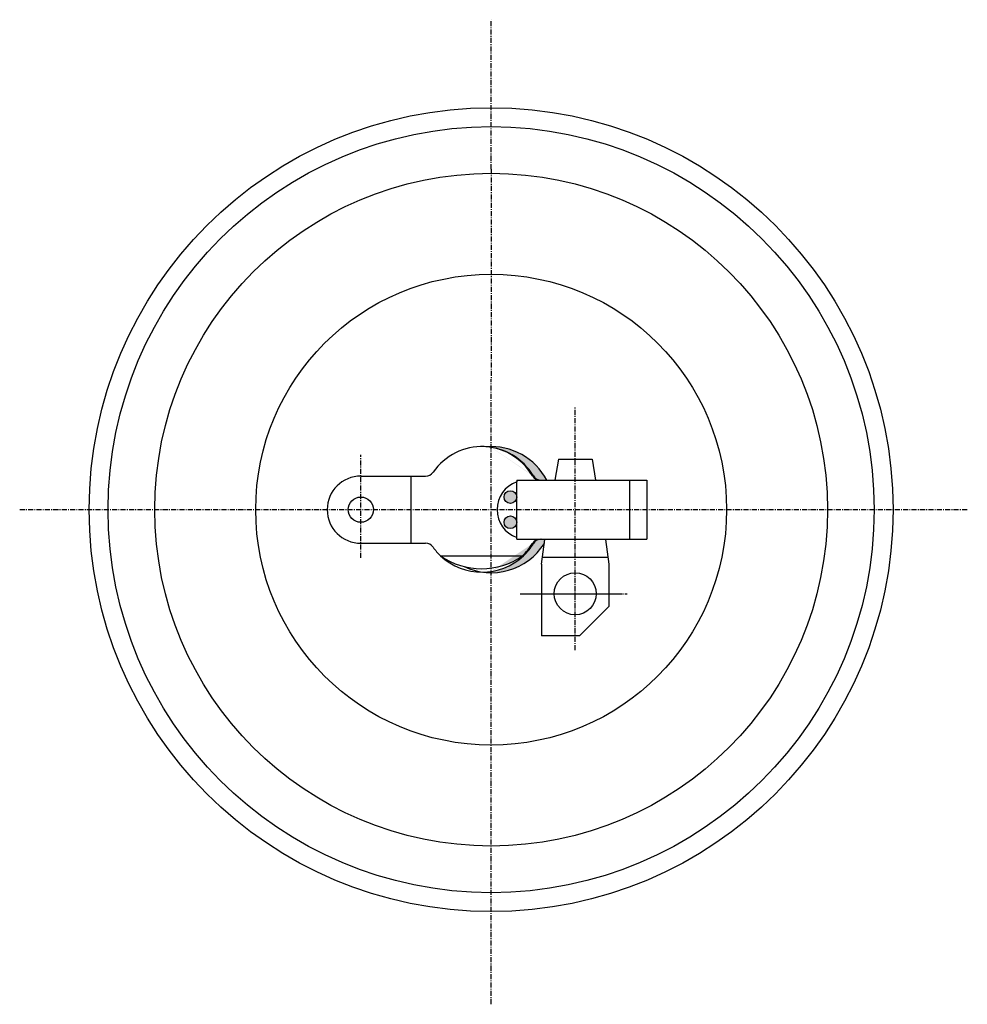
# Model space of a CAD drawing. Units: millimetres. Extents: x -91 to 198, y -189 to 190.
# Drawn here: x -56 to 57, y -189 to -72 of the extents above; entities that cross this region are included whole.
import ezdxf

# ---------------------------------------------------------------- set-up
doc = ezdxf.new("R2010")
doc.units = ezdxf.units.MM
doc.header["$LTSCALE"] = 0.2
doc.linetypes.add('ACAD_ISO10W100', pattern=[18, 12, -3, 0, -3])

msp = doc.modelspace()

# ---------------------------------------------------------------- hatches: boundary and pattern name
at = {"lineweight": 18, "ltscale": 0.25}
h = msp.add_hatch(color=7, dxfattribs=at)
edge = h.paths.add_edge_path()
edge.add_line((0, -122.5), (0, -122.584))
edge.add_ellipse((-1.082, -130), major_axis=(0, 7.5), ratio=0.9659258, start_angle=302.45069, end_angle=351.413, ccw=False)
edge.add_arc((5.969, -125.4), 1.1, 211.55802, 270)
edge.add_line((5.969, -126.5), (6.633, -126.5))
edge.add_arc((0, -130), 7.5, 27.81814, 90)
edge = h.paths.add_edge_path()
edge.add_line((6.33, -134.022), (6.394, -133.544))
edge.add_line((6.394, -133.544), (6.402, -133.5))
edge.add_line((6.402, -133.5), (5.969, -133.5))
edge.add_arc((5.969, -134.6), 1.1, 90, 148.44198)
edge.add_ellipse((-1.082, -130), major_axis=(0, 7.5), ratio=0.9659258, start_angle=222.83343, end_angle=237.54931, ccw=False)
edge.add_arc((-1.082, -130.134), 7.284, 278.54057, 312.54904, ccw=False)
edge.add_line((0, -137.337), (0, -137.5))
edge.add_arc((0, -130), 7.5, 270, 327.57078)
at = {"lineweight": 30, "ltscale": 0.25}
h = msp.add_hatch(color=7, dxfattribs=at)
h.paths.add_polyline_path([(3.044, -131.5, 1), (1.544, -131.5, 1)])
h.paths.add_polyline_path([(3.044, -128.5, 1), (1.544, -128.5, 1)])

# ---------------------------------------------------------------- linework, layer by layer
at = {"color": 1, "linetype": 'ACAD_ISO10W100', "lineweight": 25, "ltscale": 0.25}
for p, q in [((0, -89.5), (0, -71.729)), ((0, -89.5), (0, -114.5)), ((0, -188.826), (0, -114.5)), ((10, -146.709), (10, -117.805)), ((-15.5, -135.735), (-15.5, -123.466)), ((-56.068, -130), (0, -130)), ((0, -130), (56.63, -130)), ((10, -145.735), (10, -133.466)), ((3.47, -140), (15.563, -140)), ((3.892, -140), (16.16, -140))]:
    msp.add_line(p, q, dxfattribs=at)
at = {"color": 7, "lineweight": 30, "ltscale": 0.25}
for p, q in [((8, -124), (7.579, -126.5)), ((8, -124), (12, -124)), ((12, -124), (12.421, -126.5)), ((-15.5, -126), (-7.801, -126)), ((-9.5, -134), (-9.5, -126)), ((3.044, -126.5), (3.044, -126.697)), ((3.044, -126.5), (18.504, -126.5)), ((3.044, -133.303), (3.044, -126.697)), ((16.479, -133.5), (16.479, -126.5)), ((18.504, -126.5), (18.504, -133.5)), ((3.044, -133.5), (3.044, -133.303)), ((-15.5, -134), (-7.801, -134)), ((3.044, -133.5), (18.504, -133.5)), ((6, -136.5), (6.394, -133.544)), ((6.402, -133.5), (6.394, -133.544)), ((13.606, -133.544), (6.394, -133.544)), ((13.598, -133.5), (13.606, -133.544)), ((13.606, -133.544), (14, -136.5)), ((-6.007, -135.5), (3.742, -135.5)), ((6.114, -135.646), (13.886, -135.646)), ((6, -136.5), (6, -145)), ((14, -136.5), (14, -141.5)), ((14, -141.5), (10.5, -145)), ((10.5, -145), (6, -145))]:
    msp.add_line(p, q, dxfattribs=at)
for centre, radius in [((0, -130), 47.8), ((0, -130), 45.55), ((0, -130), 40), ((0, -130), 28), ((-15.5, -130), 1.5), ((-15.5, -130), 1.5), ((2.294, -128.5), 0.75), ((2.294, -131.5), 0.75), ((10, -140), 2.5)]:
    msp.add_circle(centre, radius, dxfattribs=at)
for centre, radius, start, end in [((0, -130), 7.5, 27.81814, 94.2504), ((-15.5, -130), 4, 90, 270), ((-7.801, -124.9), 1.1, 270, 324.45142), ((5.842, -125.4), 1.1, 211.09329, 270), ((5.969, -125.4), 1.1, 211.55802, 270), ((4.202, -130), 3.5, 109.32965, 250.67035), ((-7.801, -135.1), 1.1, 35.54858, 90), ((0, -130), 7.5, 244.53556, 327.57078), ((5.842, -134.6), 1.1, 90, 148.90671), ((5.969, -134.6), 1.1, 90, 148.44198), ((-1.082, -130.134), 7.284, 227.45096, 312.54904), ((-1.133, -128.513), 8.519, 235.0987, 304.9013)]:
    msp.add_arc(centre, radius, start, end, dxfattribs=at)
for ratio, start_param, end_param in [(0.9659258, 5.2787604, 7.2170531), (0.9459258, 5.2799651, 6.2831853), (0.9659258, 2.2077249, 2.3940083), (0.9459258, 10.1723623, 10.4279982), (0.9659258, 3.889177, 4.1460175)]:
    msp.add_ellipse((-1.082, -130), major_axis=(0, 7.5), ratio=ratio, start_param=start_param, end_param=end_param, dxfattribs=at)

doc.saveas('drawing.dxf')
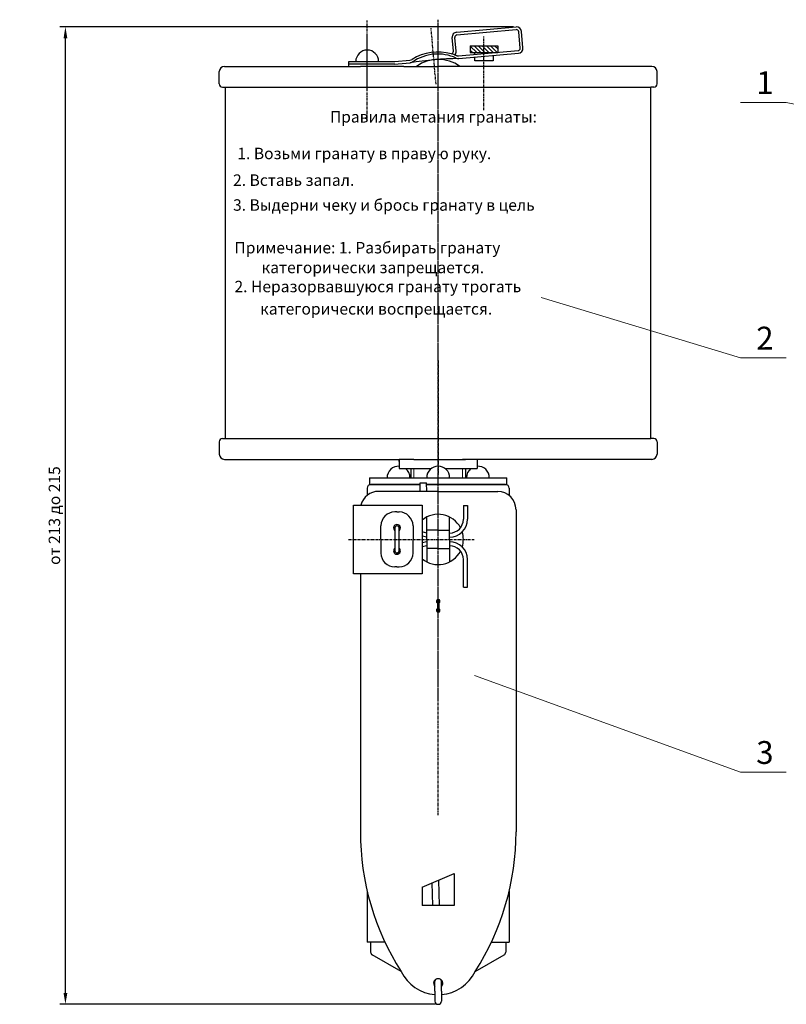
# Model space of a CAD drawing. Units: millimetres. Extents: x -91 to 198, y -189 to 190.
# Drawn here: x -91 to 76, y -26 to 189 of the extents above; entities that cross this region are included whole.
import ezdxf

# ---------------------------------------------------------------- set-up
doc = ezdxf.new("R2010")
doc.units = ezdxf.units.MM
doc.header["$LTSCALE"] = 0.2
doc.linetypes.add('ACAD_ISO02W100', pattern=[15, 12, -3])
doc.linetypes.add('ACAD_ISO10W100', pattern=[18, 12, -3, 0, -3])
doc.dimstyles.new('ISO-25', dxfattribs={"dimtxt": 2.5, "dimasz": 2.5, "dimexe": 1.25, "dimexo": 0.625, "dimtad": 1, "dimtxsty": 'Standard', "dimcen": 2.5, "dimadec": 0, "dimazin": 0, "dimtfac": 1, "dimtmove": 0, "dimatfit": 3, "dimfxl": 0, "dimarcsym": 0})

# ---------------------------------------------------------------- blocks, each defined once
blk = doc.blocks.new('*D17')
at = {"color": 0, "lineweight": -2, "ltscale": 0.25}
for p, q in [((16.47, 187.58), (-82.66, 187.58)), ((-81.41, -23.54), (-81.41, 185.08)), ((-0.62, -26.04), (-82.66, -26.04))]:
    blk.add_line(p, q, dxfattribs=at)
at = {"color": 0, "lineweight": 15, "ltscale": 0.25}
for points in [[(-81.82, 185.08), (-80.99, 185.08), (-81.41, 187.58)], [(-81.82, -23.54), (-80.99, -23.54), (-81.41, -26.04)]]:
    blk.add_solid(points, dxfattribs=at)
at = {"layer": 'Defpoints', "color": 0, "lineweight": 15, "ltscale": 0.25}
for p in [(-81.41, 187.58), (17.09, 187.58), (0, -26.04)]:
    blk.add_point(p, dxfattribs=at)
at = {"color": 0, "lineweight": 15, "ltscale": 0.25, "insert": (-83.49, 80.77), "char_height": 2.5, "attachment_point": 5, "rotation": 90}
blk.add_mtext('от 213 до 215', dxfattribs=at)

msp = doc.modelspace()

# ---------------------------------------------------------------- hatches: boundary and pattern name
at = {"lineweight": 15, "ltscale": 0.25}
h = msp.add_hatch(dxfattribs=at)
h.set_pattern_fill('ANSI31', scale=0.2, angle=90, style=0)
h.paths.add_polyline_path([(10, 183.458), (6.99, 183.458), (6.99, 181.958), (7.597, 181.962), (10, 181.979)])
h.paths.add_polyline_path([(13.01, 183.458), (10, 183.458), (10, 181.979), (13.01, 182.001)])

# ---------------------------------------------------------------- linework, layer by layer
at = {"color": 1, "linetype": 'ACAD_ISO10W100', "lineweight": 25, "ltscale": 0.25}
for p, q in [((-15.5, 167.569), (-15.5, 188.958)), ((-0.468, 175.05), (-1.55, 187.271)), ((0, 114.826), (0, 189.152)), ((0, 114.632), (0, 188.958)), ((-15.5, 173.673), (-15.5, 185.941)), ((10, 169.36), (10, 185.462)), ((0, 40.5), (0, 114.826)), ((0, 114.632), (0, 89.632)), ((0, 15.306), (0, 89.632)), ((-19.616, 75.558), (7.876, 75.558))]:
    msp.add_line(p, q, dxfattribs=at)
at = {"color": 7, "lineweight": 30, "ltscale": 0.25}
for p, q in [((4.047, 186.425), (16.996, 187.572)), ((3.313, 182.245), (3.048, 185.232)), ((3.91, 182.299), (3.646, 185.285)), ((4.1, 185.827), (17.049, 186.974)), ((17.908, 182.937), (17.591, 186.52)), ((18.504, 183.01), (18.189, 186.573)), ((6.99, 183.458), (13.01, 183.458)), ((6.99, 183.458), (6.99, 181.958)), ((13.01, 183.458), (13.01, 182.001)), ((4.424, 181.241), (17.455, 182.394)), ((4.503, 180.666), (17.506, 181.817)), ((6.99, 181.958), (7.597, 181.962)), ((7.597, 181.962), (13.01, 182.001)), ((8, 181.562), (8, 181.557)), ((8, 180.158), (8, 180.975)), ((12, 181.33), (12, 180.158)), ((-46.675, 178.958), (-27.79, 178.958)), ((-27.79, 178.958), (-17, 178.958)), ((-19.5, 179.408), (-19.5, 180.008)), ((-19.5, 180.008), (-9.5, 180.008)), ((-19.5, 178.958), (-19.5, 179.408)), ((-11.5, 179.408), (-19.5, 179.408)), ((-9.5, 179.408), (-19.5, 179.408)), ((-14, 178.958), (-17, 178.958)), ((-7.5, 178.958), (-14, 178.958)), ((-9.604, 179.417), (-6.143, 179.723)), ((-9.5, 180.008), (-6.17, 180.303)), ((-7.5, 178.958), (0, 178.958)), ((-6.143, 179.723), (-6.137, 179.724)), ((7.5, 178.958), (0, 178.958)), ((14, 178.958), (6, 178.958)), ((27.79, 178.958), (7.5, 178.958)), ((12, 180.158), (8, 180.158)), ((46.675, 178.958), (27.79, 178.958)), ((-47.8, 175.108), (-47.8, 177.833)), ((47.8, 175.108), (47.8, 177.833)), ((-47.125, 174.433), (-46.45, 174.433)), ((-46.45, 97.583), (-46.45, 174.433)), ((-46.45, 174.433), (46.45, 174.433)), ((47.125, 174.433), (46.45, 174.433)), ((46.45, 97.583), (46.45, 174.433)), ((-47.8, 96.908), (-47.8, 94.183)), ((-47.125, 97.583), (-46.45, 97.583)), ((-46.45, 97.583), (46.45, 97.583)), ((47.125, 97.583), (46.45, 97.583)), ((47.8, 96.908), (47.8, 94.183)), ((-46.681, 93.058), (-27.79, 93.058)), ((-27.79, 93.058), (-8.499, 93.058)), ((-8.5, 93.058), (-8.499, 93.058)), ((-8.5, 92.608), (-8.5, 93.058)), ((-8.5, 93.058), (-8.5, 91.058)), ((-6, 93.058), (-8.5, 93.058)), ((-5.3, 93.058), (-6, 93.058)), ((-5.3, 93.058), (5.3, 93.058)), ((6, 93.058), (5.3, 93.058)), ((5.3, 93.058), (6, 93.058)), ((8.5, 93.058), (6, 93.058)), ((27.79, 93.058), (8.5, 93.058)), ((8.5, 93.058), (8.5, 92.608)), ((8.5, 93.058), (8.5, 91.058)), ((46.675, 93.058), (27.79, 93.058)), ((-8.5, 91.058), (-1.5, 91.058)), ((-6, 91.058), (-6, 89.058)), ((1.5, 91.058), (8.5, 91.058)), ((6, 91.058), (6, 89.058)), ((-15, 89.058), (15, 89.058)), ((-15, 89.058), (-15, 87.558)), ((15, 87.558), (15, 89.058)), ((-15.5, 86.758), (-15.5, 85.18)), ((-15, 87.558), (-3.945, 87.558)), ((-3.945, 87.558), (-14.7, 87.558)), ((-3.9, 86.058), (-3.957, 87.958)), ((-3.957, 87.958), (-2.557, 87.958)), ((-2.5, 86.058), (-2.557, 87.958)), ((-2.5, 87.558), (-2.545, 87.558)), ((14.7, 87.558), (-2.5, 87.558)), ((-2.5, 87.558), (15, 87.558)), ((15.5, 86.758), (15.5, 85.18)), ((0, 86.058), (-13, 86.058)), ((0, 86.058), (13, 86.058)), ((-18.5, 68.058), (-18.5, 83.058)), ((-18.5, 83.058), (-3.5, 83.058)), ((-3.5, 83.058), (-3.5, 68.058)), ((5.5, 82.958), (6.4, 82.958)), ((5.5, 82.958), (5.5, 79.958)), ((6.4, 82.958), (6.4, 79.958)), ((17, 82.058), (17, 11.661)), ((-9, 81.558), (-9.5, 81.558)), ((-9, 81.558), (-8.5, 81.558)), ((-2.5, 75.558), (-2.5, 80.457)), ((2.5, 75.558), (2.5, 80.457)), ((-12.5, 75.558), (-12.5, 78.558)), ((-9.45, 78.058), (-9.45, 73.058)), ((-8.311, 78.355), (-8.895, 78.495)), ((-8.55, 73.058), (-8.55, 78.058)), ((-8.52, 77.482), (-8.55, 77.489)), ((-5.5, 78.558), (-5.5, 75.558)), ((0, 77.558), (-2.5, 77.558)), ((0, 77.558), (2.5, 77.558)), ((-12.5, 75.558), (-12.5, 72.558)), ((-5.5, 72.558), (-5.5, 75.558)), ((-2.5, 76.958), (-3.5, 77.198)), ((-2.5, 76.058), (-3.5, 76.294)), ((-2.5, 75.558), (-2.5, 70.659)), ((2.5, 75.558), (2.5, 70.659)), ((-8.52, 73.634), (-8.55, 73.627)), ((-2.5, 75.058), (-3.5, 74.821)), ((-2.5, 74.158), (-3.5, 73.917)), ((0, 73.558), (-2.5, 73.558)), ((0, 73.558), (2.5, 73.558)), ((-8.311, 72.761), (-8.895, 72.62)), ((5.5, 65.158), (5.5, 71.158)), ((6.4, 65.158), (6.4, 71.158)), ((-9, 69.558), (-9.5, 69.558)), ((-9, 69.558), (-8.5, 69.558)), ((-3.5, 68.058), (-18.5, 68.058)), ((-17, 68.058), (-17, 11.661)), ((5.5, 65.158), (6.4, 65.158)), ((-0.15, 62.058), (-0.15, 60.058)), ((0.15, 62.058), (0.15, 60.058)), ((-3.5, -0.442), (3.5, 2.558)), ((3.5, 2.558), (3.5, -4.442)), ((-1.195, -4.442), (-1.342, 0.483)), ((0.04, 1.075), (0.205, -4.442)), ((-15.5, -1.307), (-15.5, -12.442)), ((-3.5, -0.442), (-3.5, -4.442)), ((15.5, -1.307), (15.5, -12.442)), ((3.5, -4.442), (-3.5, -4.442)), ((-11.633, -12.442), (-15.5, -12.442)), ((-14.75, -12.442), (-14.75, -14.63)), ((11.633, -12.442), (15.5, -12.442)), ((14.75, -12.442), (14.75, -14.63)), ((-8.094, -18.877), (-14.4, -15.237)), ((8.094, -18.877), (14.4, -15.237)), ((-0.7, -23.192), (-0.7, -20.986)), ((0.7, -23.192), (0.7, -20.992)), ((-0.7, -23.192), (-0.7, -25.342)), ((0.7, -23.192), (0.7, -25.342))]:
    msp.add_line(p, q, dxfattribs=at)
at = {"color": 7, "linetype": 'ACAD_ISO02W100', "lineweight": 25, "ltscale": 0.25}
msp.add_line((8, 181.958), (8, 181.965), dxfattribs=at)
at = {"color": 7, "lineweight": 15, "ltscale": 0.25}
for p, q in [((66.022, 171.087), (76.022, 171.087)), ((76.022, 171.087), (148.204, 156.278)), ((66.022, 115.259), (22.469, 128.446)), ((66.022, 115.259), (76.022, 115.259)), ((-5.3, 91.058), (-5.3, 89.058)), ((5.3, 91.058), (5.3, 89.058)), ((66.022, 24.701), (7.952, 45.802)), ((66.022, 24.701), (76.022, 24.701))]:
    msp.add_line(p, q, dxfattribs=at)
at = {"color": 7, "lineweight": 30, "ltscale": 0.25}
for centre, radius, start, end in [((17.093, 186.476), 1.1, 5.06, 95.06), ((4.144, 185.329), 1.1, 95.06, 185.06), ((4.144, 185.329), 0.5, 95.06, 185.06), ((17.093, 186.476), 0.5, 5.06, 95.06), ((17.41, 182.893), 0.5, 275.06, 5.06), ((17.409, 182.913), 1.1, 275.06, 5.06), ((-15.5, 180.008), 2.5, 0, 180), ((-0.055, 171.551), 10.543, 74.25589, 122.24423), ((-0.083, 171.875), 9.758, 65.57806, 124.54194), ((2.815, 182.201), 0.5, 275.06, 5.06), ((-2.301, 165.972), 16.556, 67.95295, 71.84305), ((2.814, 182.202), 1.1, 315.98814, 5.06), ((-0.055, 171.551), 10.543, 66.46415, 69.6852), ((4.327, 182.336), 1.1, 247.95295, 275.06), ((7.6, 181.562), 0.4, 0, 90.41011), ((-46.675, 177.833), 1.125, 90, 180), ((-6.267, 181.398), 1.1, 275.06, 302.24423), ((-6.24, 180.819), 1.1, 275.06, 304.54194), ((5.624, 107.564), 73.111, 90.8788, 99.23559), ((4.406, 181.762), 1.1, 245.57806, 275.06), ((46.675, 177.833), 1.125, 0, 90), ((-47.125, 175.108), 0.675, 180, 270), ((47.125, 175.108), 0.675, 270, 0), ((-47.125, 96.908), 0.675, 90, 180), ((47.125, 96.908), 0.675, 0, 90), ((-46.675, 94.183), 1.125, 180, 270), ((-47, 94.508), 1.45, 276.78123, 276.84585), ((46.675, 94.183), 1.125, 270, 0), ((-8.66, 89.058), 2.5, 86.32473, 180), ((-8.66, 89.058), 2.5, 0, 53.1301), ((0, 89.058), 2.5, 0, 180), ((8.66, 89.058), 2.5, 126.8699, 180), ((8.66, 89.058), 2.5, 0, 93.67527), ((-14.7, 86.758), 0.8, 90, 180), ((14.7, 86.758), 0.8, 0, 90), ((-13, 82.058), 4, 90, 165.52249), ((13, 82.058), 4, 0, 90), ((-9.5, 78.558), 3, 90, 180), ((-8.5, 78.558), 3, 0, 90), ((0, 75.558), 5.5, 27.72539, 129.5212), ((2.5, 79.958), 3, 270, 0), ((2.5, 79.958), 3.9, 270, 0), ((-9, 78.058), 0.75, 306.8699, 233.1301), ((-9, 78.058), 0.45, 0, 180), ((0, 75.558), 5.5, 342.69829, 17.30171), ((-9, 73.058), 0.75, 126.8699, 53.1301), ((2.5, 71.158), 3.9, 0, 90), ((2.5, 71.158), 3, 0, 90), ((-9.5, 72.558), 3, 180, 270), ((-9, 73.058), 0.45, 180, 0), ((-8.5, 72.558), 3, 270, 0), ((0, 75.558), 5.5, 230.4788, 332.27461), ((0, 62.058), 0.4, 292.02431, 247.97569), ((0, 60.058), 0.4, 112.02431, 67.97569), ((0, 62.058), 0.15, 0, 180), ((0, 60.058), 0.15, 180, 0), ((39.812, 11.661), 56.812, 180, 212.51617), ((-39.812, 11.661), 56.812, 327.48383, 0), ((-14.05, -14.63), 0.7, 180, 240), ((14.05, -14.63), 0.7, 300, 0), ((0, -14.942), 9, 205.92801, 265.53916), ((0, -14.942), 9, 274.46084, 334.07199), ((0, -21.442), 1, 314.427, 225.573), ((0, -20.992), 0.7, 150.78454, 180), ((0, -20.992), 0.7, 0, 29.21546), ((0, -25.342), 0.7, 180, 0)]:
    msp.add_arc(centre, radius, start, end, dxfattribs=at)
at = {"color": 7, "linetype": 'ByBlock', "lineweight": 30}
msp.add_arc((0, 172.258), 8.2, 54.79287, 125.20713, dxfattribs=at)

# ---------------------------------------------------------------- texts
at = {"color": 7, "lineweight": 15, "ltscale": 0.25}
for s, p in [('1', (69.455, 172.876)), ('2', (69.455, 117.047)), ('3', (69.455, 26.489))]:
    msp.add_text(s, height=5, dxfattribs=at).set_placement(p)
at = {"color": 7, "lineweight": 30, "ltscale": 0.25}
for s, p in [('Правила метания гранаты:', (-23.643, 166.672)), ('1. Возьми гранату в правую руку.', (-43.865, 158.667)), ('2. Вставь запал.', (-44.798, 152.839)), ('3. Выдерни чеку и брось гранату в цель', (-44.798, 147.398)), ('Примечание: 1. Разбирать гранату', (-44.487, 138.073)), ('категорически запрещается.', (-38.576, 133.75)), ('2. Неразорвавшуюся гранату трогать', (-44.487, 129.584)), ('категорически воспрещается.', (-38.887, 124.705))]:
    msp.add_text(s, height=2.5, dxfattribs=at).set_placement(p)

# ---------------------------------------------------------------- dimensions: what is measured, and where the dimension line sits
at = {"color": 3, "lineweight": 15, "ltscale": 0.25}
dim = msp.add_linear_dim(base=(-81.405, 187.576), p1=(0, -26.042), p2=(17.093, 187.576), angle=90, text='от 213 до 215', dimstyle='ISO-25', dxfattribs=at)
dim.commit()
dim.dimension.update_dxf_attribs({"geometry": '*D17', "text_midpoint": (-83.489, 80.767)})

doc.saveas('drawing.dxf')
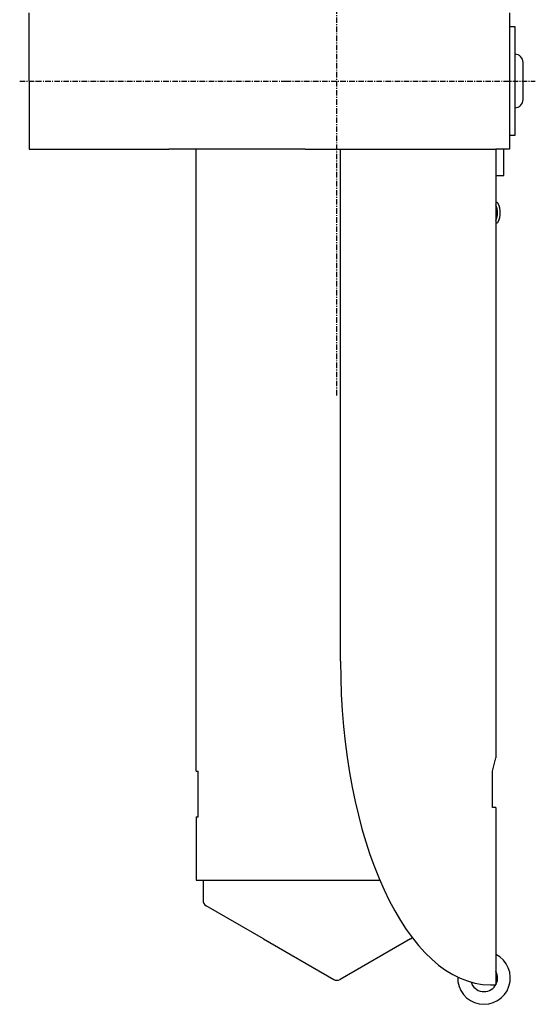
# Model space of a CAD drawing. Units: millimetres. Extents: x -91 to 198, y -189 to 190.
# Drawn here: x 115 to 172, y -26 to 82 of the extents above; entities that cross this region are included whole.
import ezdxf

# ---------------------------------------------------------------- set-up
doc = ezdxf.new("R2010")
doc.units = ezdxf.units.MM
doc.header["$LTSCALE"] = 0.2
doc.linetypes.add('ACAD_ISO10W100', pattern=[18, 12, -3, 0, -3])

msp = doc.modelspace()

# ---------------------------------------------------------------- linework, layer by layer
at = {"color": 1, "linetype": 'ACAD_ISO10W100', "lineweight": 25, "ltscale": 0.25}
for p, q in [((150, 40.94999999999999), (150, 115.2760053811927)), ((115.0527369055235, 75.55779463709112), (116.8716337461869, 75.55779463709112)), ((116.8716337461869, 75.55779463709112), (144.3634335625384, 75.55779463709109)), ((144.3634335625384, 75.55779463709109), (171.8552333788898, 75.55779463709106))]:
    msp.add_line(p, q, dxfattribs=at)
at = {"color": 7, "lineweight": 30, "ltscale": 0.25}
for p, q in [((116.1, 75.55779463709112), (116.1, 83.05779463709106)), ((169.0000030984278, 83.05779463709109), (169.0000030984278, 68.05779463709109)), ((169.0000030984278, 81.55779463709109), (169.6000030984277, 81.55779463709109)), ((169.6000030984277, 81.55779463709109), (169.6000030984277, 69.55779463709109)), ((170.5000030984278, 73.50779463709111), (170.5000030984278, 77.60779463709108)), ((116.1, 75.55779463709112), (116.1, 68.05779463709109)), ((169.6000030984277, 69.55779463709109), (169.0000030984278, 69.55779463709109)), ((116.1, 68.05779463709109), (131.5, 68.05779463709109)), ((146.5, 68.05779463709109), (131.5, 68.05779463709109)), ((134.5, -0.4422053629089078), (134.5, 68.05779463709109)), ((146.5, 68.05779463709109), (167.5000030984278, 68.05779463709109)), ((150.4000030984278, 11.68323594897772), (150.4000030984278, 68.05779463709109)), ((169.0000030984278, 68.05779463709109), (167.5000030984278, 68.05779463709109)), ((167.5000030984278, 68.05779463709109), (167.5000030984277, 1.057794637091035)), ((168.4000030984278, 65.15779463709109), (168.4000030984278, 68.05779463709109)), ((167.5000030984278, 65.15779463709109), (168.4000030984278, 65.15779463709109)), ((167.1400042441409, -0.4431136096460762), (167.5000030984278, 1.057794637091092)), ((134.5, -0.4422053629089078), (134.7, -0.4422053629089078)), ((134.7, -5.442205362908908), (134.7, -0.4422053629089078)), ((167.1400030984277, -4.442205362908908), (167.1400042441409, -0.4431136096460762)), ((167.5000030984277, -4.442205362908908), (167.1400030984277, -4.442205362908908)), ((167.5000030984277, -4.442205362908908), (167.5000030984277, -23.94220536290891)), ((134.5, -5.442205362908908), (134.7, -5.442205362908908)), ((134.5, -5.442205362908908), (134.5, -12.44220536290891)), ((134.5, -12.44220536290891), (154.7296343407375, -12.44220536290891)), ((135.25, -12.44220536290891), (135.25, -14.63044685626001)), ((141.9059031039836, -18.87737949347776), (135.6, -15.23666463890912)), ((141.9059031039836, -18.87737949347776), (149.6500007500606, -23.34842357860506)), ((158.0940968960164, -18.87737949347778), (150.3499992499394, -23.34842357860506)), ((158.0940968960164, -18.87737949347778), (158.3052730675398, -18.75545687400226)), ((166.9000030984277, -23.94220536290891), (167.4990302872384, -23.94388780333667))]:
    msp.add_line(p, q, dxfattribs=at)
for centre, radius, start, end in [((169.6000030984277, 77.60779463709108), 0.9, 0, 90), ((169.6000030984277, 73.50779463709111), 0.9, 270, 0), ((165.7982421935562, 61.05779463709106), 1.9, 333.4586685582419, 26.54133144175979), ((167.5000030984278, 61.90779463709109), 0.3000000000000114, 29.9999999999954, 90), ((165.7982421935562, 61.05779463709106), 2.201760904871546, 332.9876899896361, 27.0123100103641), ((167.5000030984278, 60.2077946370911), 0.3000000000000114, 270, 329.9999999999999), ((135.95, -14.63044685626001), 0.7, 180, 239.9999999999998), ((166.2009649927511, -23.19220536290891), 2.9, 177.8820447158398, 63.38813937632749), ((166.2009649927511, -23.19220536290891), 1.5, 197.4351235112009, 30), ((150, -22.7422053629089), 0.7, 240.0000708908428, 299.9999291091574)]:
    msp.add_arc(centre, radius, start, end, dxfattribs=at)
msp.add_ellipse((167, 11.66135114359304), major_axis=(-0.09999690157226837, -35.60355650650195), ratio=0.4662436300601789, start_param=4.713083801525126, end_param=6.283185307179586, dxfattribs=at)

doc.saveas('drawing.dxf')
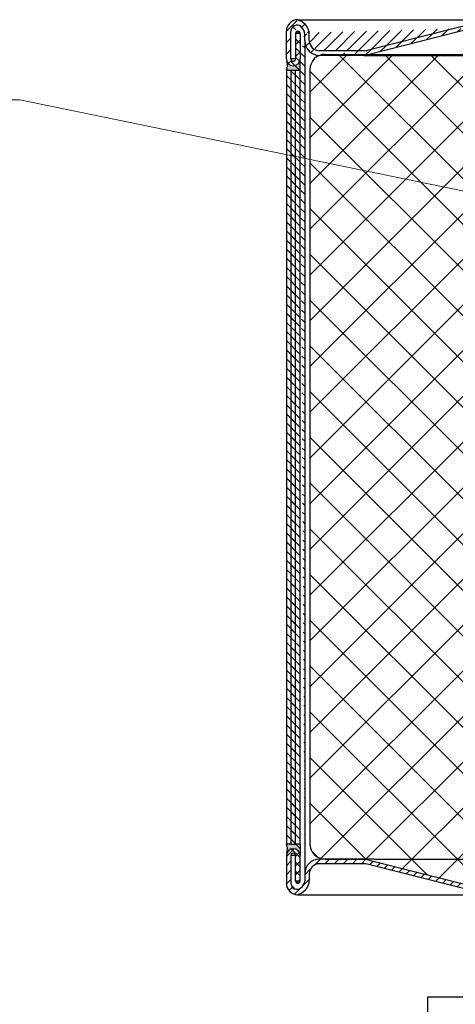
# Model space of a CAD drawing. Units: millimetres. Extents: x -91 to 198, y -189 to 190.
# Drawn here: x 76 to 119, y 82 to 179 of the extents above; entities that cross this region are included whole.
import ezdxf

# ---------------------------------------------------------------- set-up
doc = ezdxf.new("R2010")
doc.units = ezdxf.units.MM
doc.header["$LTSCALE"] = 0.2
pattern_1 = [(135, (0, 0), (-0.4490128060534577, -0.4490128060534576), [])]

msp = doc.modelspace()

# ---------------------------------------------------------------- hatches: boundary and pattern name
at = {"lineweight": 15, "ltscale": 0.25}
h = msp.add_hatch(dxfattribs=at)
h.set_pattern_fill('ANSI31', scale=0.25, style=0)
h.set_pattern_definition([(45, (150, 0), (-0.561266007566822, 0.5612660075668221), [])])
edge = h.paths.add_edge_path()
edge.add_line((103.55, 177.6077946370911), (103.1, 177.6077946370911))
edge.add_line((103.55, 177.6077946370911), (103.55, 175.1077946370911))
edge.add_line((103.1, 177.6077946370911), (103.1, 175.1077946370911))
edge.add_arc((102.875, 175.1077946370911), 0.6750000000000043, 180, 360)
edge.add_arc((102.875, 175.1077946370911), 0.2250000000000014, 180, 360)
edge.add_line((102.65, 175.1077946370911), (102.65, 177.6077946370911))
edge.add_line((102.2, 175.1077946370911), (102.2, 177.8327946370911))
edge.add_arc((103.325, 177.8327946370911), 1.125, 90, 180)
edge.add_arc((103.25, 177.8200445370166), 0.6, 51.31781254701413, 180)
edge.add_arc((103, 177.5077946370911), 1.45, 0, 83.21876594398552)
edge.add_arc((103, 177.5077946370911), 1, 0, 51.31781254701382)
edge.add_line((104, 176.9077946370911), (104, 177.5077946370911))
edge.add_line((104.4499998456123, 176.9077947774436), (104.45, 177.5077946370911))
edge.add_arc((105.45, 176.9077946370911), 1.45, 180, 270)
edge.add_arc((105.4499998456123, 176.9077946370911), 1, 179.9999919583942, 270)
edge.add_line((109.855185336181, 175.9077946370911), (105.4499998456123, 175.9077946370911))
edge.add_line((109.7900187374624, 175.4577946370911), (105.45, 175.4577946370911))
edge.add_arc((109.855185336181, 176.9077946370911), 1, 270, 286.4799732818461)
edge.add_arc((109.7900187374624, 176.9077946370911), 1.45, 269.9999999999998, 286.4799732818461)
edge.add_line((121.8611344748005, 178.4667135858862), (110.2013550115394, 175.5173621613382))
edge.add_line((121.7986449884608, 178.898227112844), (110.1388655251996, 175.9488756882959))
edge.add_arc((122.2099812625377, 177.5077946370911), 1.45, 90, 106.4799732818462)
edge.add_arc((122.1448146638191, 177.5077946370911), 1, 90, 106.4799732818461)
edge.add_line((133, 178.5077946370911), (122.1448146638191, 178.5077946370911))
edge.add_line((122.2099812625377, 178.9577946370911), (133, 178.9577946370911))
edge.add_line((133, 178.9577946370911), (133, 178.5077946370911))
h = msp.add_hatch(dxfattribs=at)
h.set_pattern_fill('ANSI31', scale=0.2, angle=90, style=0)
h.set_pattern_definition(pattern_1)
edge = h.paths.add_edge_path()
edge.add_line((103.1, 175.1077946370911), (102.65, 175.1077946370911))
edge.add_line((103.1, 177.6077946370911), (103.1, 175.1077946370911))
edge.add_line((102.65, 175.1077946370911), (102.65, 177.6077946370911))
edge.add_arc((103.25, 177.8200445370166), 0.6, 51.31781254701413, 180)
edge.add_arc((103.325, 177.6077946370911), 0.2250000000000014, 0, 180)
edge.add_line((103.55, 177.6077946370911), (103.55, 175.1077946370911))
edge.add_arc((103, 177.5077946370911), 1, 0, 51.31781254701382)
edge.add_line((104, 176.9077946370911), (104, 177.5077946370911))
edge.add_line((104, 176.9077946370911), (104, 94.40779463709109))
edge.add_line((103.55, 174.0127946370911), (103.55, 175.1077946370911))
edge.add_line((103.55, 98.01279463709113), (103.55, 174.0127946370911))
edge.add_line((103.55, 98.01279463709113), (103.55, 96.90779463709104))
edge.add_line((103.55, 94.40779463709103), (103.55, 96.90779463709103))
edge.add_arc((103.325, 94.40779463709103), 0.2250000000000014, 180, 360)
edge.add_arc((103.25, 94.19554473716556), 0.6, 180, 308.6821874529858)
edge.add_line((102.65, 94.40779463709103), (102.65, 94.19554473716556))
edge.add_line((102.65, 96.90779463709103), (102.65, 94.40779463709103))
edge.add_line((103.1, 94.40779463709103), (103.1, 96.90779463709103))
edge.add_line((103.1, 96.90779463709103), (102.65, 96.90779463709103))
for points in [[(103.55, 175.1077946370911, -0.8066543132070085), (102.2604534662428, 174.8285858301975, -0.159301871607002), (102.2, 174.0127946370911), (102.65, 174.0127946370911), (103.1, 174.0127946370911), (103.55, 174.0127946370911)], [(103.55, 98.01279463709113), (103.1, 98.01279463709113), (102.65, 98.01279463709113), (102.2, 98.01279463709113, -0.1703818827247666), (102.2427745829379, 97.14426032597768, -0.08957544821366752), (102.3654272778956, 97.35046905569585, -0.693844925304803), (103.55, 96.90779463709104)]]:
    msp.add_hatch(color=7, dxfattribs=at).paths.add_polyline_path(points)
h = msp.add_hatch(dxfattribs=at)
h.set_pattern_fill('ANSI37', style=0)
h.set_pattern_definition([(45, (0, 0), (-2.245064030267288, 2.245064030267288), []), (135, (0, 0), (-2.245064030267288, -2.245064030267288), [])])
edge = h.paths.add_edge_path()
edge.add_line((143.5, 173.5577946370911), (141.6, 175.4577946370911))
edge.add_line((141.6, 175.4577946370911), (109.7900187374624, 175.4577946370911))
edge.add_line((109.7900187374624, 175.4577946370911), (105.4614835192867, 175.4577946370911))
edge.add_arc((106, 174.057794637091), 1.5, 111.0394697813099, 180)
edge.add_line((104.5, 174.057794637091), (104.5, 98.05779463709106))
edge.add_arc((106, 98.05779463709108), 1.5, 180.0000000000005, 270)
edge.add_line((106, 96.55779463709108), (109.7900187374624, 96.55779463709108))
edge.add_arc((109.7900187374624, 95.10779463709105), 1.450000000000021, 73.52002671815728, 90, ccw=False)
edge.add_line((110.2013550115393, 96.49822711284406), (120, 94.01965128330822))
edge.add_line((120, 94.01965128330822), (120, 94.69779463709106))
edge.add_line((120, 94.69779463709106), (120, 96.55779463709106))
edge.add_line((120, 96.55779463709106), (137.9871730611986, 96.55779463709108))
edge.add_spline(control_points=[(137.9871730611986, 96.55779463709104), (138.0397711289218, 96.90154095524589), (138.0998945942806, 97.24357800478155), (138.172001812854, 97.58279463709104)], knot_values=[3.513574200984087, 3.513574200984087, 3.513574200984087, 3.513574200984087, 4.553471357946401, 4.553471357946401, 4.553471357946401, 4.553471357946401], degree=3, periodic=0)
edge.add_spline(control_points=[(138.172001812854, 97.58279463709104), (138.3326873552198, 98.33871352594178), (138.9005402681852, 100.2520026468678), (140.7570590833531, 102.7504300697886), (142.6575824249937, 103.3928231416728), (143.5000000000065, 103.5745058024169)], knot_values=[4.553471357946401, 4.553471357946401, 4.553471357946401, 4.553471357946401, 6.870804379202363, 10.52954648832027, 13.14244180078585, 13.14244180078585, 13.14244180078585, 13.14244180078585], degree=3, periodic=0)
edge.add_line((143.5, 103.5745058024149), (143.5, 173.5577946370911))
edge = h.paths.add_edge_path()
edge.add_arc((194, 174.0577946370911), 1.5, 0, 68.9605302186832)
edge.add_line((194.5385164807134, 175.4577946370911), (190.2099812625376, 175.4577946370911))
edge.add_line((190.2099812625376, 175.4577946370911), (158.4000000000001, 175.4577946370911))
edge.add_line((158.4000000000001, 175.4577946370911), (156.5, 173.557794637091))
edge.add_line((156.5, 173.557794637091), (156.5, 107.293329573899))
edge.add_spline(control_points=[(156.5, 107.293329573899), (159.568356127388, 107.2734474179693), (166.2472937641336, 100.5987291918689), (177.8374551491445, 99.56551382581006), (187.1937075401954, 102.0382007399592), (193.2277025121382, 104.4777862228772), (195.4999999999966, 103.8812710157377)], knot_values=[26.56510633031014, 26.56510633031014, 26.56510633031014, 26.56510633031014, 36.92141533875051, 50.22349476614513, 59.82893242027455, 67.1271089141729, 67.1271089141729, 67.1271089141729, 67.1271089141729], degree=3, periodic=0)
edge.add_line((195.5, 103.8812710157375), (195.5, 174.0577946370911))
h = msp.add_hatch(dxfattribs=at)
h.set_pattern_fill('ANSI31', scale=0.2, angle=90, style=0)
h.set_pattern_definition(pattern_1)
h.paths.add_polyline_path([(102.2, 174.0127946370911), (102.2, 98.01279463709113), (102.65, 98.01279463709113), (103.1, 98.01279463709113), (103.55, 98.01279463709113), (103.55, 174.0127946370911), (103.1, 174.0127946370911), (102.65, 174.0127946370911)])
h = msp.add_hatch(dxfattribs=at)
h.set_pattern_fill('ANSI31', scale=0.2, style=0)
h.set_pattern_definition([(45, (0, 0), (-0.4490128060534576, 0.4490128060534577), [])])
edge = h.paths.add_edge_path()
edge.add_arc((102.875, 96.90779463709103), 0.2249999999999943, 0, 180, ccw=False)
edge.add_line((103.1, 96.90779463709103), (103.1, 94.40779463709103))
edge.add_line((103.1, 94.40779463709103), (103.55, 94.40779463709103))
edge.add_line((103.55, 94.40779463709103), (103.55, 96.90779463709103))
edge.add_arc((102.875, 96.90779463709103), 0.6750000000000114, 0, 180)
edge.add_line((102.2, 96.90779463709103), (102.2, 94.18279463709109))
edge.add_arc((103.325, 94.18279463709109), 1.125, 180, 262.2266208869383)
edge.add_arc((103, 94.5077946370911), 1.450000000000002, 276.8458494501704, 360.0000147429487)
edge.add_line((104.45, 94.50779501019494), (104.4499998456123, 95.10779437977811))
edge.add_arc((105.4499998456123, 95.1077946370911), 0.9999999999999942, 90, 180.0000147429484, ccw=False)
edge.add_line((105.4499998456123, 96.10779463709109), (109.855185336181, 96.1077946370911))
edge.add_arc((109.855185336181, 95.1077946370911), 0.9999999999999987, 73.52002671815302, 90.0000000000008, ccw=False)
edge.add_line((110.1388655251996, 96.06671358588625), (121.7986449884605, 93.11736216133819))
edge.add_arc((122.2099812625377, 94.50779463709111), 1.450000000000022, 253.5200267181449, 270)
edge.add_line((122.2099812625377, 93.05779463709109), (137.5397852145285, 93.05779463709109))
edge.add_spline(control_points=[(137.5397852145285, 93.05779463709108), (137.5627773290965, 93.20743537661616), (137.5843313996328, 93.35746623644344), (137.6048188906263, 93.5077946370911)], knot_values=[0, 0, 0, 0, 0.4541903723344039, 0.4541903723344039, 0.4541903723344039, 0.4541903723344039], degree=3, periodic=0)
edge.add_line((137.6048188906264, 93.50779463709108), (132.2171286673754, 93.50779463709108))
edge.add_line((132.2171286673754, 93.50779463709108), (122.1448146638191, 93.5077946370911))
edge.add_arc((122.1448146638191, 94.5077946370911), 0.9999999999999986, 253.52002671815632, 269.9999999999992, ccw=False)
edge.add_line((121.8611344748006, 93.54887568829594), (110.2013550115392, 96.49822711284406))
edge.add_arc((109.7900187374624, 95.10779463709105), 1.450000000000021, 73.52002671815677, 89.99999999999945)
edge.add_line((109.7900187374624, 96.55779463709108), (105.45, 96.55779463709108))
edge.add_arc((105.45, 95.10779463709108), 1.450000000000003, 90.00000000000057, 180)
edge.add_line((104, 95.10779463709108), (104, 94.5077946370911))
edge.add_line((104, 94.5077946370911), (104, 94.40779463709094))
edge.add_arc((103.0620265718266, 94.48096639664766), 0.940823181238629, 306.7542392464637, 355.53936257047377, ccw=False)
edge.add_arc((103.25, 94.19554473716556), 0.5999999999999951, 180, 308.68218745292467, ccw=False)
edge.add_line((102.65, 94.19554473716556), (102.65, 94.40779463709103))
edge.add_line((102.65, 94.40779463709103), (102.65, 96.90779463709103))

# ---------------------------------------------------------------- linework, layer by layer
at = {"color": 7, "lineweight": 30, "ltscale": 0.25}
for p, q in [((103.325, 178.9577946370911), (122.2099812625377, 178.9577946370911)), ((121.7986449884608, 178.898227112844), (110.1388655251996, 175.9488756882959)), ((121.8611344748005, 178.4667135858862), (110.2013550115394, 175.5173621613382)), ((102.2, 175.1077946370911), (102.2, 177.8327946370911)), ((102.65, 177.6077946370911), (102.65, 177.8200445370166)), ((102.65, 175.1077946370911), (102.65, 177.6077946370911)), ((103.55, 177.6077946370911), (103.1, 177.6077946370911)), ((103.1, 177.6077946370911), (103.1, 175.1077946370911)), ((103.55, 177.6077946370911), (103.55, 175.1077946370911)), ((104, 176.9077946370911), (104, 177.5077946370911)), ((104, 176.9077946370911), (104, 94.40779463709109)), ((104.4499998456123, 176.9077947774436), (104.45, 177.5077946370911)), ((104.45, 177.5077946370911), (104.45, 177.5077946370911)), ((109.855185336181, 175.9077946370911), (105.4499998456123, 175.9077946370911)), ((103.1, 175.1077946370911), (102.65, 175.1077946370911)), ((103.55, 174.0127946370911), (103.55, 175.1077946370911)), ((109.7900187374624, 175.4577946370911), (105.45, 175.4577946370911)), ((106, 175.557794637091), (143.55, 175.557794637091)), ((109.7900187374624, 175.4577946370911), (143.55, 175.4577946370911)), ((102.2, 174.0127946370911), (102.65, 174.0127946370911)), ((102.2, 174.0127946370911), (102.2, 98.01279463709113)), ((102.65, 174.0127946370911), (103.1, 174.0127946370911)), ((102.65, 174.0127946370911), (102.65, 98.01279463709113)), ((103.1, 174.0127946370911), (103.55, 174.0127946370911)), ((103.1, 98.01279463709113), (103.1, 174.0127946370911)), ((103.55, 98.01279463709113), (103.55, 174.0127946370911)), ((104.5, 174.057794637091), (104.5, 98.05779463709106)), ((102.65, 98.01279463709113), (102.2, 98.01279463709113)), ((102.65, 98.01279463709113), (103.1, 98.01279463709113)), ((103.55, 98.01279463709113), (103.1, 98.01279463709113)), ((103.55, 98.01279463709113), (103.55, 96.90779463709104)), ((102.2, 96.90779463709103), (102.2, 94.18279463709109)), ((102.65, 96.90779463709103), (102.65, 94.40779463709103)), ((103.1, 96.90779463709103), (102.65, 96.90779463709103)), ((103.1, 94.40779463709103), (103.1, 96.90779463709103)), ((103.55, 94.4077946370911), (103.55, 96.90779463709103)), ((103.55, 94.40779463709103), (103.55, 96.90779463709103)), ((109.855185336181, 96.1077946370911), (105.4499998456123, 96.10779463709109)), ((109.7900187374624, 96.55779463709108), (105.45, 96.55779463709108)), ((106, 96.55779463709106), (109.7900187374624, 96.55779463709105)), ((110.8087323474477, 96.55779463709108), (109.9106791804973, 96.55779463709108)), ((121.7986449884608, 93.11736216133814), (110.1388655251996, 96.06671358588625)), ((110.2013550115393, 96.49822711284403), (121.8611344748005, 93.54887568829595)), ((110.8087323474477, 96.55779463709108), (137.9871730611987, 96.55779463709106)), ((111.2162555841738, 96.55779463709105), (137.9871730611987, 96.55779463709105)), ((104, 95.10779463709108), (104, 94.5077946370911)), ((104.4499998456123, 95.10779449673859), (104.45, 94.50779501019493)), ((102.65, 94.40779463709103), (102.65, 94.19554473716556)), ((103.55, 94.40779463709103), (103.1, 94.40779463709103)), ((104.45, 94.5077946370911), (104.45, 94.5077946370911)), ((103.3185330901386, 93.05779463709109), (122.2099812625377, 93.05779463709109)), ((116.1, 75.55779463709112), (116.1, 83.05779463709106)), ((116.1, 83.05779463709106), (131.5, 83.05779463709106))]:
    msp.add_line(p, q, dxfattribs=at)
at = {"color": 7, "lineweight": 15, "ltscale": 0.25}
for p, q in [((66.02203149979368, 171.0874822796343), (76.02203149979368, 171.0874822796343)), ((76.02203149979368, 171.0874822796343), (148.2039487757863, 156.2775385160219))]:
    msp.add_line(p, q, dxfattribs=at)
at = {"color": 7, "lineweight": 30, "ltscale": 0.25}
for centre, radius, start, end in [((103.325, 177.8327946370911), 1.125, 90, 180), ((103, 177.5077946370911), 1.45, 0, 83.21876594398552), ((103.25, 177.8200445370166), 0.6, 51.31781254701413, 180), ((103, 177.5077946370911), 1, 0, 51.31781254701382), ((103.325, 177.6077946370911), 0.2250000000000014, 0, 180), ((105.45, 176.9077946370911), 1.45, 180, 270), ((105.4499998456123, 176.9077946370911), 1, 179.9999919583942, 270), ((109.855185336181, 176.9077946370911), 1, 270, 286.4799732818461), ((102.875, 175.1077946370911), 0.6750000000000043, 180, 0), ((102.875, 175.1077946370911), 0.2250000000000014, 180, 0), ((106, 174.057794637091), 1.5, 90, 180), ((109.7900187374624, 176.9077946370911), 1.45, 269.9999999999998, 286.4799732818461), ((100.9824560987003, 174.5131551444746), 1.316348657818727, 337.6593520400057, 13.86443725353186), ((100.9839893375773, 97.51758667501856), 1.312978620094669, 343.480871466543, 22.15811012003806), ((106, 98.05779463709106), 1.5, 180, 270), ((102.875, 96.90779463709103), 0.6749999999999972, 0, 180), ((102.875, 96.90779463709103), 0.6750000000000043, 139.0186029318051, 180), ((102.875, 96.90779463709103), 0.2250000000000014, 0, 180), ((105.45, 95.10779463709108), 1.45, 90, 180), ((105.4499998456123, 95.10779463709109), 1, 90, 180.0000080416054), ((109.7900187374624, 95.10779463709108), 1.45, 73.52002671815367, 90), ((109.855185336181, 95.1077946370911), 1, 73.52002671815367, 90), ((103.325, 94.18279463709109), 1.125, 180, 270), ((103.25, 94.19554473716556), 0.6, 180, 308.6821874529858), ((103.325, 94.40779463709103), 0.2250000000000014, 180, 0), ((103, 94.5077946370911), 1.45, 276.7812340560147, 0), ((103, 94.50779463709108), 1.45, 276.7812340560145, 0), ((103.0620265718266, 94.48096639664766), 0.9408231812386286, 306.7542392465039, 355.5393625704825)]:
    msp.add_arc(centre, radius, start, end, dxfattribs=at)

doc.saveas('drawing.dxf')
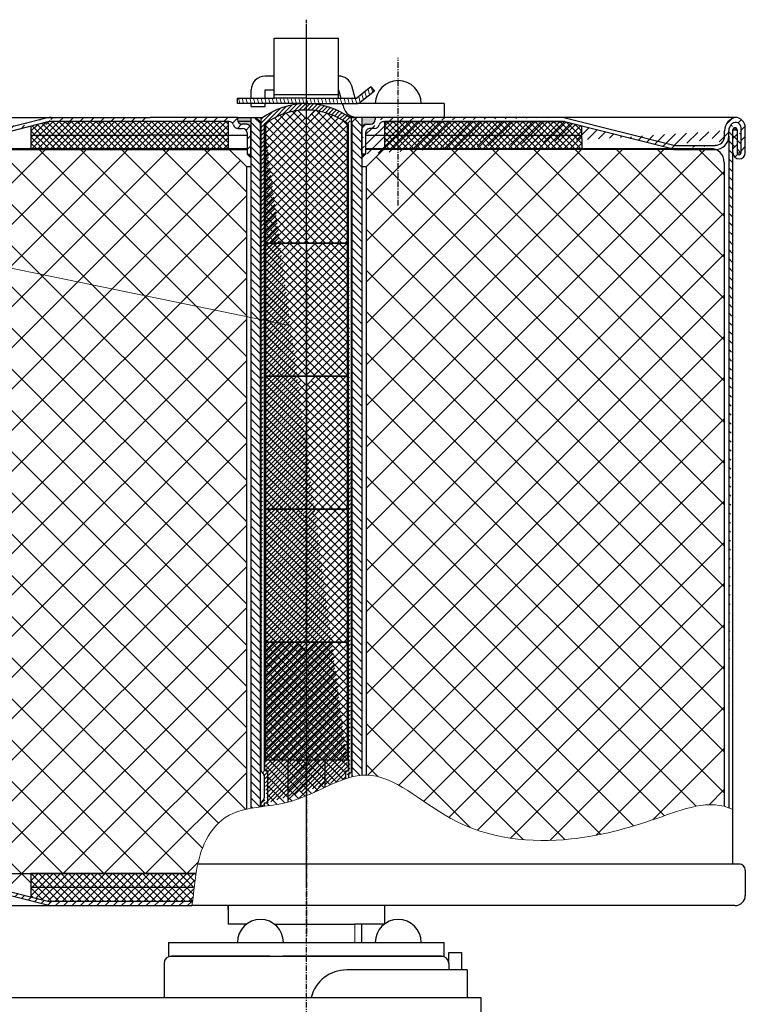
# Model space of a CAD drawing. Units: millimetres. Extents: x -91 to 198, y -189 to 190.
# Drawn here: x 119 to 198, y 82 to 190 of the extents above; entities that cross this region are included whole.
import ezdxf

# ---------------------------------------------------------------- set-up
doc = ezdxf.new("R2010")
doc.units = ezdxf.units.MM
doc.header["$LTSCALE"] = 0.2
doc.linetypes.add('ACAD_ISO10W100', pattern=[18, 12, -3, 0, -3])
pattern_1 = [(45, (150, 0), (-0.561266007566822, 0.5612660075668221), [])]
pattern_2 = [(45, (150.0000000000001, 108.9577946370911), (-0.4490128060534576, 0.4490128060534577), []), (135, (150.0000000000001, 108.9577946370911), (-0.4490128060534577, -0.4490128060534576), [])]
pattern_3 = [(135, (0, 0), (-0.4939140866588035, -0.4939140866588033), [])]

# ---------------------------------------------------------------- blocks, each defined once
blk = doc.blocks.new('tetril_stolbik_8_92')
at = {"lineweight": 15, "ltscale": 0.25}
h = blk.add_hatch(dxfattribs=at)
h.set_pattern_fill('ANSI37', scale=0.2, angle=90, style=0)
h.set_pattern_definition([(135, (0, 0), (-0.4490128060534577, -0.4490128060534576), []), (225, (0, 0), (0.4490128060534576, -0.4490128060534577), [])])
h.paths.add_polyline_path([(4.469813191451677e-15, 14.5), (-4.46, 14.5), (-4.46, 5.461744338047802e-16), (-1, 5.461744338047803e-16), (3.367667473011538e-16, 1)])
h.paths.add_polyline_path([(4.460000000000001, 14.5), (4.469813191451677e-15, 14.5), (3.367667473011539e-16, 1), (1, 5.461744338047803e-16), (4.46, 5.461744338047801e-16)])
at = {"color": 1, "linetype": 'ACAD_ISO10W100', "lineweight": 25, "ltscale": 0.25}
blk.add_line((-1.224606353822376e-16, -0.4999999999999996), (7.53132907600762e-15, 24.5), dxfattribs=at)
at = {"color": 7, "lineweight": 30, "ltscale": 0.25}
for p, q in [((-4.46, 5.461744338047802e-16), (-4.459999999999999, 14.5)), ((4.460000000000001, 14.5), (-4.459999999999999, 14.5)), ((4.46, 5.461744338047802e-16), (4.460000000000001, 14.5)), ((-4.46, 5.461744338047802e-16), (4.46, 5.461744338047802e-16)), ((-1, 5.461744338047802e-16), (3.367667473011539e-16, 1)), ((3.367667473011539e-16, 1), (1, 5.461744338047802e-16))]:
    blk.add_line(p, q, dxfattribs=at)

msp = doc.modelspace()

# ---------------------------------------------------------------- hatches: boundary and pattern name
at = {"lineweight": 15, "ltscale": 0.25}
h = msp.add_hatch(dxfattribs=at)
h.set_pattern_fill('ANSI31', scale=0.125, angle=59.99999999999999, style=0)
h.set_pattern_definition([(105, (0, 0.1906555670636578), (-0.3833518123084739, -0.1027188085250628), [])])
h.paths.add_polyline_path([(150, 181.0554563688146), (149.9470806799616, 181.0554563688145), (146.5, 181.0554563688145), (142.5, 181.0554563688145), (142.5, 180.4577946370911), (146.5, 180.4577946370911), (150, 180.457794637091)])
h.paths.add_polyline_path([(157.4177141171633, 181.8234116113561), (157.032088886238, 182.2844799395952), (155.5, 181.0554563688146), (153.5, 181.0554563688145), (150, 181.0554563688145), (150, 180.4577946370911), (153.5, 180.4577946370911), (155.5, 180.457794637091, 0.1702187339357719), (155.8732023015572, 180.5886377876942)])
h = msp.add_hatch(dxfattribs=at)
h.set_pattern_fill('ANSI31', scale=0.1, style=0)
h.set_pattern_definition([(45, (0, 0), (-0.2245064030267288, 0.2245064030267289), [])])
edge = h.paths.add_edge_path()
edge.add_line((145.4250000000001, 103.8835345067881), (145.0900000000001, 103.8383460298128))
edge.add_line((145.4250000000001, 103.8835345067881), (145.4250000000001, 104.2577946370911))
edge.add_line((145.0900000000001, 103.8383460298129), (145.0900000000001, 104.2577946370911))
edge.add_arc((145.4250000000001, 104.2577946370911), 0.3350000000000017, 119.7398696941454, 180)
edge.add_arc((145.1100000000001, 104.8091565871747), 0.3, 299.7398696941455, 360)
edge.add_arc((145.5500000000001, 104.4577946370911), 0.2000000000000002, 270, 360)
edge.add_line((145.7500000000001, 107.7577946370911), (145.7500000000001, 104.2577946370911))
edge.add_line((145.4100000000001, 107.2064326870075), (145.4100000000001, 104.8091565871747))
edge.add_arc((145.1100000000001, 107.2064326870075), 0.3, 0, 60.26013030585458)
edge.add_arc((145.4250000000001, 107.7577946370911), 0.3350000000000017, 180, 240.2601303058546)
edge.add_arc((145.5500000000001, 107.5577946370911), 0.2000000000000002, 0, 90)
edge.add_line((145.7500000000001, 107.7577946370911), (145.4250000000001, 107.7577946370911))
edge.add_line((145.4250000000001, 104.2577946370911), (145.7500000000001, 104.2577946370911))
edge.add_line((145.4250000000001, 107.7577946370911), (145.4250000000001, 178.2008052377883))
edge.add_line((145.0900000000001, 107.7577946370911), (145.0900000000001, 178.8252827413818))
edge.add_arc((150.0000000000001, 172.2577946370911), 8.200000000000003, 53.21739364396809, 126.7826063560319)
edge.add_arc((150.0000000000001, 172.2577946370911), 7.5, 52.41049703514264, 127.5895029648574)
edge.add_line((154.5750000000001, 107.7577946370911), (154.5750000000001, 178.2008052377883))
edge.add_line((154.9100000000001, 107.7577946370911), (154.9100000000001, 178.8252827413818))
edge.add_arc((154.5750000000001, 107.7577946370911), 0.3350000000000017, 299.7398696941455, 360)
edge.add_arc((154.8900000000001, 107.2064326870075), 0.3, 119.7398696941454, 180)
edge.add_line((154.5900000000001, 107.2064326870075), (154.5900000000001, 106.9857708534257))
edge.add_line((154.2500000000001, 107.7577946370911), (154.5750000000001, 107.7577946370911))
edge.add_arc((154.4500000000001, 107.5577946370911), 0.2000000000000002, 90, 180)
edge.add_line((154.2500000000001, 107.7577946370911), (154.2500000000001, 106.8772143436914))
at = {"linetype": 'ByBlock', "lineweight": 15}
h = msp.add_hatch(dxfattribs=at)
h.set_pattern_fill('ANSI37', scale=0.2, style=0)
h.set_pattern_definition(pattern_2)
h.paths.add_polyline_path([(150.0000000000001, 178.7577946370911), (149.0592363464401, 179.6985582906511, 0.1284710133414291), (145.5400000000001, 178.2875873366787), (145.5400000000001, 165.2577946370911), (150.0000000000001, 165.2577946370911)])
h.paths.add_polyline_path([(154.4600000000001, 178.2875873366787, 0.1284710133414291), (150.9407636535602, 179.6985582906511), (150.9287125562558, 179.6865071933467), (150.0000000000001, 178.7577946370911), (150.0000000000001, 165.2577946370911), (154.4600000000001, 165.2577946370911)])
at = {"lineweight": 15, "ltscale": 0.25}
h = msp.add_hatch(dxfattribs=at)
h.set_pattern_fill('ANSI31', scale=0.25, style=0)
h.set_pattern_definition(pattern_1)
edge = h.paths.add_edge_path()
edge.add_line((103.55, 177.6077946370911), (103.1, 177.6077946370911))
edge.add_line((103.55, 177.6077946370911), (103.55, 175.1077946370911))
edge.add_line((103.1, 177.6077946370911), (103.1, 175.1077946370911))
edge.add_arc((102.875, 175.1077946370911), 0.6750000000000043, 180, 360)
edge.add_arc((102.875, 175.1077946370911), 0.2250000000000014, 180, 360)
edge.add_line((102.65, 175.1077946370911), (102.65, 177.6077946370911))
edge.add_line((102.2, 175.1077946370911), (102.2, 177.8327946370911))
edge.add_arc((103.325, 177.8327946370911), 1.125, 90, 180)
edge.add_arc((103.25, 177.8200445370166), 0.6, 51.31781254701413, 180)
edge.add_arc((103, 177.5077946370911), 1.45, 0, 83.21876594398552)
edge.add_arc((103, 177.5077946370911), 1, 0, 51.31781254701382)
edge.add_line((104, 176.9077946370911), (104, 177.5077946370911))
edge.add_line((104.4499998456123, 176.9077947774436), (104.45, 177.5077946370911))
edge.add_arc((105.45, 176.9077946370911), 1.45, 180, 270)
edge.add_arc((105.4499998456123, 176.9077946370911), 1, 179.9999919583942, 270)
edge.add_line((109.855185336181, 175.9077946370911), (105.4499998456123, 175.9077946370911))
edge.add_line((109.7900187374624, 175.4577946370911), (105.45, 175.4577946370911))
edge.add_arc((109.855185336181, 176.9077946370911), 1, 270, 286.4799732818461)
edge.add_arc((109.7900187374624, 176.9077946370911), 1.45, 269.9999999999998, 286.4799732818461)
edge.add_line((121.8611344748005, 178.4667135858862), (110.2013550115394, 175.5173621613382))
edge.add_line((121.7986449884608, 178.898227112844), (110.1388655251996, 175.9488756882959))
edge.add_arc((122.2099812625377, 177.5077946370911), 1.45, 90, 106.4799732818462)
edge.add_arc((122.1448146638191, 177.5077946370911), 1, 90, 106.4799732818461)
edge.add_line((133, 178.5077946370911), (122.1448146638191, 178.5077946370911))
edge.add_line((122.2099812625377, 178.9577946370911), (133, 178.9577946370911))
edge.add_line((133, 178.9577946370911), (133, 178.5077946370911))
h = msp.add_hatch(dxfattribs=at)
h.set_pattern_fill('ANSI37', scale=0.15, style=0)
h.set_pattern_definition([(135, (150, 0), (0.3367596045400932, 0.3367596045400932), []), (45.00000000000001, (150, 0), (0.3367596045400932, -0.3367596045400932), [])])
h.paths.add_polyline_path([(120, 177.995937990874), (121.8611344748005, 178.4667135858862, -0.07203164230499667), (122.1448146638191, 178.5077946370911), (140, 178.5077946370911), (140, 177.0327946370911), (120, 177.0327946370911)])
h.paths.add_polyline_path([(120, 176.6477946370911), (120, 177.032794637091), (140, 177.0327946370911), (140, 175.557794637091), (120, 175.557794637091)])
h.paths.add_polyline_path([(140, 178.5077946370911), (141.5, 178.5077946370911), (141.5, 177.032794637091), (140, 177.032794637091)])
h.paths.add_polyline_path([(140, 177.0327946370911), (141.5, 177.0327946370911), (141.5, 176.6477946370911), (141.5, 175.557794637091), (140, 175.557794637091)])
h = msp.add_hatch(dxfattribs=at)
h.set_pattern_fill('ANSI31', scale=0.25, style=0)
h.set_pattern_definition([(45, (150, 74.13178925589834), (-0.561266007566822, 0.5612660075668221), [])])
edge = h.paths.add_edge_path()
edge.add_line((136, 178.9577946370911), (136, 178.5077946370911))
edge.add_line((141.5817541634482, 178.5077946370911), (136, 178.5077946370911))
edge.add_arc((141.5817541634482, 178.0077946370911), 0.5, 14.47751218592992, 90)
edge.add_arc((142.55, 178.2577946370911), 0.5, 194.47751218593, 270)
edge.add_line((142.55, 177.7577946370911), (143.05, 177.7577946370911))
edge.add_arc((143.05, 177.2577946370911), 0.5, 0, 90)
edge.add_line((143.55, 177.2577946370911), (143.55, 174.9577946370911))
edge.add_line((143.55, 174.9577946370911), (143.95, 174.9577946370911))
edge.add_line((143.95, 174.9577946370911), (143.95, 177.7077946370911))
edge.add_arc((143.45, 177.7077946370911), 0.5, 0, 90.0000000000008)
edge.add_line((143.5, 178.2077946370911), (143, 178.2077946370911))
edge.add_arc((143, 178.7077946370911), 0.5, 180, 270)
edge.add_line((142.5, 178.9577946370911), (142.5, 178.7077946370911))
edge.add_line((142.5, 178.9577946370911), (136, 178.9577946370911))
at = {"lineweight": 18, "ltscale": 0.25}
for points in [[(143.95, 178.957794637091), (142.5, 178.9577946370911), (142.5, 178.7077946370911, 0.4142135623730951), (143, 178.2077946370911), (143.45, 178.2077946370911, -0.4142135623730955), (143.95, 177.7077946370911)], [(157.5, 178.7077946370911), (157.5, 178.9577946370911), (156.05, 178.9577946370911), (156.05, 177.7077946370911, -0.4142135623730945), (156.55, 178.2077946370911), (157, 178.2077946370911, 0.4142135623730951)]]:
    msp.add_hatch(color=7, dxfattribs=at).paths.add_polyline_path(points)
at = {"lineweight": 15, "ltscale": 0.25}
h = msp.add_hatch(dxfattribs=at)
h.set_pattern_fill('ANSI31', scale=0.2, angle=90, style=0)
h.set_pattern_definition([(135, (0, 0), (-0.4490128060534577, -0.4490128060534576), [])])
edge = h.paths.add_edge_path()
edge.add_line((145, 178.4577946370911), (144.5, 178.9577946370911))
edge.add_line((144.5, 178.9577946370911), (143.95, 178.9577946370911))
edge.add_line((143.95, 178.9577946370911), (143.95, 103.6632302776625))
edge.add_spline(control_points=[(143.9500000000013, 103.6632302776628), (144.2940625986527, 103.7253542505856), (144.645004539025, 103.7770577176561), (145.0000000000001, 103.8260032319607)], knot_values=[13.60306095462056, 13.60306095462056, 13.60306095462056, 13.60306095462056, 14.6497497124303, 14.6497497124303, 14.6497497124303, 14.6497497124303], degree=3, periodic=0)
edge.add_line((145, 103.8260032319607), (145, 178.4577946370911))
edge = h.paths.add_edge_path()
edge.add_line((156.05, 178.957794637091), (155.5, 178.9577946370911))
edge.add_line((155.5, 178.9577946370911), (155, 178.4577946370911))
edge.add_line((155, 178.4577946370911), (155, 107.0985468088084))
edge.add_spline(control_points=[(155.0000000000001, 107.0985468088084), (155.3522582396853, 107.1861188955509), (155.7021320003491, 107.2479253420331), (156.05, 107.2761614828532)], knot_values=[24.89151301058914, 24.89151301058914, 24.89151301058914, 24.89151301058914, 26.06002268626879, 26.06002268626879, 26.06002268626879, 26.06002268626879], degree=3, periodic=0)
edge.add_line((156.05, 107.2761614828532), (156.05, 178.957794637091))
at = {"lineweight": 18, "ltscale": 0.25}
h = msp.add_hatch(dxfattribs=at)
h.set_pattern_fill('ANSI31', scale=0.25, style=0)
h.set_pattern_definition(pattern_1)
edge = h.paths.add_edge_path()
edge.add_line((196.45, 177.6077946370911), (196.9, 177.6077946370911))
edge.add_line((196.45, 175.1077946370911), (196.45, 177.6077946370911))
edge.add_line((196.9, 177.6077946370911), (196.9, 175.1077946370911))
edge.add_arc((197.125, 175.1077946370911), 0.2250000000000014, 180, 360)
edge.add_arc((197.125, 175.1077946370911), 0.6750000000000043, 180, 360)
edge.add_line((197.8, 175.1077946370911), (197.8, 177.832794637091))
edge.add_line((197.35, 175.1077946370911), (197.35, 177.6077946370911))
edge.add_line((197.35, 177.6077946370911), (197.35, 177.8200445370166))
edge.add_arc((196.75, 177.8200445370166), 0.6, 0, 128.6821874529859)
edge.add_arc((196.675, 177.832794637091), 1.125, 0, 89.99999999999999)
edge.add_arc((197, 177.5077946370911), 1.45, 96.8458494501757, 180)
edge.add_arc((197, 177.5077946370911), 1, 128.6821874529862, 180)
edge.add_line((196, 176.9077946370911), (196, 177.5077946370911))
edge.add_line((195.5500001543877, 176.9077947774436), (195.55, 177.5077942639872))
edge.add_arc((194.55, 176.9077946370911), 1.45, 270, 360)
edge.add_arc((194.5500001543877, 176.9077946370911), 1, 270, 360.0000080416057)
edge.add_line((190.144814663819, 175.9077946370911), (194.5500001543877, 175.9077946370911))
edge.add_line((190.2099812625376, 175.4577946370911), (194.55, 175.4577946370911))
edge.add_arc((190.144814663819, 176.9077946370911), 1, 253.5200267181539, 270)
edge.add_arc((190.2099812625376, 176.9077946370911), 1.45, 253.5200267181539, 270.0000000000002)
edge.add_line((189.7986449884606, 175.5173621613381), (178.1388655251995, 178.4667135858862))
edge.add_line((178.2013550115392, 178.898227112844), (189.8611344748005, 175.9488756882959))
edge.add_arc((177.7900187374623, 177.5077946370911), 1.45, 73.52002671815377, 89.99999999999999)
edge.add_arc((177.8551853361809, 177.5077946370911), 1, 73.52002671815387, 89.99999999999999)
edge.add_line((158.4182458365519, 178.5077946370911), (177.8551853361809, 178.5077946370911))
edge.add_line((177.7900187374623, 178.9577946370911), (157.5, 178.9577946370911))
edge.add_arc((158.4182458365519, 178.0077946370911), 0.5, 89.99999999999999, 165.5224878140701)
edge.add_arc((157.45, 178.2577946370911), 0.5, 270, 345.5224878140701)
edge.add_line((157.5, 178.9577946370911), (157.5, 178.7077946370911))
edge.add_arc((157, 178.7077946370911), 0.5, 270, 360)
edge.add_line((156.5, 178.2077946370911), (157, 178.2077946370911))
edge.add_arc((156.55, 177.7077946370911), 0.5, 89.99999999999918, 180)
edge.add_line((157.45, 177.7577946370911), (156.95, 177.7577946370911))
edge.add_arc((156.95, 177.2577946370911), 0.5, 89.99999999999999, 180)
edge.add_line((156.45, 177.2577946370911), (156.45, 174.9577946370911))
edge.add_line((156.05, 174.9577946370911), (156.05, 177.7077946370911))
edge.add_line((156.45, 174.9577946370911), (156.05, 174.9577946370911))
at = {"lineweight": 15, "ltscale": 0.25}
h = msp.add_hatch(dxfattribs=at)
h.set_pattern_fill('ANSI37', scale=0.15, style=0)
h.set_pattern_definition([(45, (150, 0), (-0.3367596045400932, 0.3367596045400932), []), (135, (150, 0), (-0.3367596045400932, -0.3367596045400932), [])])
h.paths.add_polyline_path([(160, 178.5077946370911), (160, 177.032794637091), (180, 177.0327946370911), (180, 177.995937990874), (178.1388655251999, 178.4667135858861, 0.07203164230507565), (177.855185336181, 178.5077946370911)])
h.paths.add_polyline_path([(160, 177.0327946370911), (160, 175.557794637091), (180, 175.557794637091), (180, 176.6477946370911), (180, 177.0327946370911)])
h.paths.add_polyline_path([(160, 178.5077946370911), (158.5, 178.5077946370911), (158.5, 177.0327946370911), (160, 177.032794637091)])
h.paths.add_polyline_path([(160, 177.032794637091), (158.5000000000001, 177.0327946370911), (158.5, 176.6477946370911), (158.5, 175.557794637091), (160, 175.557794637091)])
h = msp.add_hatch(dxfattribs=at)
h.set_pattern_fill('ANSI31', scale=0.22, angle=90, style=0)
h.set_pattern_definition(pattern_3)
edge = h.paths.add_edge_path()
edge.add_line((196.9, 175.1077946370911), (197.35, 175.1077946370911))
edge.add_line((196.9, 177.6077946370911), (196.9, 175.1077946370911))
edge.add_line((197.35, 175.1077946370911), (197.35, 177.6077946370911))
edge.add_arc((196.75, 177.8200445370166), 0.6, 0, 128.6821874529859)
edge.add_line((197.35, 177.6077946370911), (197.35, 177.8200445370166))
edge.add_arc((196.675, 177.6077946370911), 0.2250000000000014, 0, 180)
edge.add_arc((197, 177.5077946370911), 1, 128.6821874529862, 180)
edge.add_line((196, 176.9077946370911), (196, 177.5077946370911))
edge.add_line((196, 176.9077946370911), (196, 103.7205278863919))
edge.add_line((196.45, 175.1077946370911), (196.45, 177.6077946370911))
edge.add_line((196.45, 97.58279453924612), (196.45, 175.1077946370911))
h = msp.add_hatch(dxfattribs=at)
h.set_pattern_fill('ANSI37', style=0)
h.set_pattern_definition([(45, (0, 0), (-2.245064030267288, 2.245064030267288), []), (135, (0, 0), (-2.245064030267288, -2.245064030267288), [])])
edge = h.paths.add_edge_path()
edge.add_line((143.5, 173.5577946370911), (141.6, 175.4577946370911))
edge.add_line((141.6, 175.4577946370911), (109.7900187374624, 175.4577946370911))
edge.add_line((109.7900187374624, 175.4577946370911), (105.4614835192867, 175.4577946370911))
edge.add_arc((106, 174.057794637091), 1.5, 111.0394697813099, 180)
edge.add_line((104.5, 174.057794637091), (104.5, 98.05779463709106))
edge.add_arc((106, 98.05779463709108), 1.5, 180.0000000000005, 270)
edge.add_line((106, 96.55779463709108), (109.7900187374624, 96.55779463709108))
edge.add_arc((109.7900187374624, 95.10779463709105), 1.450000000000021, 73.52002671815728, 90, ccw=False)
edge.add_line((110.2013550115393, 96.49822711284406), (120, 94.01965128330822))
edge.add_line((120, 94.01965128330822), (120, 94.69779463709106))
edge.add_line((120, 94.69779463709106), (120, 96.55779463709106))
edge.add_line((120, 96.55779463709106), (137.9871730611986, 96.55779463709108))
edge.add_spline(control_points=[(137.9871730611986, 96.55779463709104), (138.0397711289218, 96.90154095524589), (138.0998945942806, 97.24357800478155), (138.172001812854, 97.58279463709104)], knot_values=[3.513574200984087, 3.513574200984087, 3.513574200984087, 3.513574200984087, 4.553471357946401, 4.553471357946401, 4.553471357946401, 4.553471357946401], degree=3, periodic=0)
edge.add_spline(control_points=[(138.172001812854, 97.58279463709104), (138.3326873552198, 98.33871352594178), (138.9005402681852, 100.2520026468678), (140.7570590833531, 102.7504300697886), (142.6575824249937, 103.3928231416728), (143.5000000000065, 103.5745058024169)], knot_values=[4.553471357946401, 4.553471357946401, 4.553471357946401, 4.553471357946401, 6.870804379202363, 10.52954648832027, 13.14244180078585, 13.14244180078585, 13.14244180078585, 13.14244180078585], degree=3, periodic=0)
edge.add_line((143.5, 103.5745058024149), (143.5, 173.5577946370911))
edge = h.paths.add_edge_path()
edge.add_arc((194, 174.0577946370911), 1.5, 0, 68.9605302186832)
edge.add_line((194.5385164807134, 175.4577946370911), (190.2099812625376, 175.4577946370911))
edge.add_line((190.2099812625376, 175.4577946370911), (158.4000000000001, 175.4577946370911))
edge.add_line((158.4000000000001, 175.4577946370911), (156.5, 173.557794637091))
edge.add_line((156.5, 173.557794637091), (156.5, 107.293329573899))
edge.add_spline(control_points=[(156.5, 107.293329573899), (159.568356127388, 107.2734474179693), (166.2472937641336, 100.5987291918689), (177.8374551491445, 99.56551382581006), (187.1937075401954, 102.0382007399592), (193.2277025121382, 104.4777862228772), (195.4999999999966, 103.8812710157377)], knot_values=[26.56510633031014, 26.56510633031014, 26.56510633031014, 26.56510633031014, 36.92141533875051, 50.22349476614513, 59.82893242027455, 67.1271089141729, 67.1271089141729, 67.1271089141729, 67.1271089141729], degree=3, periodic=0)
edge.add_line((195.5, 103.8812710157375), (195.5, 174.0577946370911))
for points in [[(143.95, 174.9577946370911), (143.55, 174.957794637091), (143.95, 174.5577946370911)], [(156.45, 174.9577946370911), (156.05, 174.9577946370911), (156.05, 174.5577946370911)]]:
    msp.add_hatch(color=7, dxfattribs=at).paths.add_polyline_path(points)
at = {"linetype": 'ByBlock', "lineweight": 15}
h = msp.add_hatch(dxfattribs=at)
h.set_pattern_fill('ANSI37', scale=0.2, style=0)
h.set_pattern_definition(pattern_2)
h.paths.add_polyline_path([(150.0000000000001, 120.7577946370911), (149.0000000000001, 121.7577946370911), (145.5400000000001, 121.7577946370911), (145.5400000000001, 108.9577946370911), (150.0000000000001, 108.9577946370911), (150.0000000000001, 109.4577946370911)])
h.paths.add_polyline_path([(154.4600000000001, 121.7577946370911), (151.0000000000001, 121.7577946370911), (150.0000000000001, 120.7577946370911), (150.0000000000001, 111.7577946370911), (150.0000000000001, 109.4577946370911), (150.0000000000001, 108.9577946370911), (154.4600000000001, 108.9577946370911)])
at = {"lineweight": 15, "ltscale": 0.25}
h = msp.add_hatch(dxfattribs=at)
h.set_pattern_fill('ANSI31', scale=0.22, angle=90, style=0)
h.set_pattern_definition(pattern_3)
edge = h.paths.add_edge_path()
edge.add_line((148.0000000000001, 108.9577946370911), (145.5400000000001, 108.9577946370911))
edge.add_line((145.5400000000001, 108.9577946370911), (145.4250000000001, 108.9577946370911))
edge.add_line((145.4250000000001, 108.9577946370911), (145.4250000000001, 107.7577946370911))
edge.add_line((145.4250000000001, 107.7577946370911), (145.7500000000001, 107.7577946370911))
edge.add_line((145.7500000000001, 107.7577946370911), (145.7500000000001, 104.2577946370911))
edge.add_line((145.7500000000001, 104.2577946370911), (145.4250000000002, 104.2577946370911))
edge.add_line((145.4250000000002, 104.2577946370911), (145.4250000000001, 103.8835345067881))
edge.add_spline(control_points=[(145.4250000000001, 103.8835345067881), (146.2794498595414, 103.9980840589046), (147.1506143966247, 104.114272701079), (147.9999999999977, 104.3364804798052)], knot_values=[15.06573433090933, 15.06573433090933, 15.06573433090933, 15.06573433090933, 17.56549764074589, 17.56549764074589, 17.56549764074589, 17.56549764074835], degree=3, periodic=0)
edge.add_line((148.0000000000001, 104.3364804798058), (148.0000000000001, 108.9577946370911))
edge = h.paths.add_edge_path()
edge.add_line((154.5750000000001, 108.9577946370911), (152.0000000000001, 108.9577946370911))
edge.add_line((152.0000000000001, 108.9577946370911), (152.0000000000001, 105.9390777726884))
edge.add_spline(control_points=[(151.9999999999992, 105.939077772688), (152.7636405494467, 106.292470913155), (153.512516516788, 106.6283473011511), (154.2500000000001, 106.8772143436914)], knot_values=[21.64438294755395, 21.64438294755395, 21.64438294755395, 21.64438294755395, 24.06630626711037, 24.06630626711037, 24.06630626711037, 24.06630626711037], degree=3, periodic=0)
edge.add_line((154.2500000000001, 106.8772143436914), (154.2500000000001, 107.7577946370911))
edge.add_line((154.2500000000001, 107.7577946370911), (154.5750000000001, 107.7577946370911))
edge.add_line((154.5750000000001, 107.7577946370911), (154.5750000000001, 108.9577946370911))
h = msp.add_hatch(dxfattribs=at)
h.set_pattern_fill('ANSI37', scale=0.22, angle=90, style=0)
h.set_pattern_definition([(135, (0, 0), (-0.4939140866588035, -0.4939140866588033), []), (225, (0, 0), (0.4939140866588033, -0.4939140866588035), [])])
edge = h.paths.add_edge_path()
edge.add_line((150.0000000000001, 108.4577946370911), (149.5000000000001, 108.9577946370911))
edge.add_line((149.5000000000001, 108.9577946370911), (148.0000000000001, 108.9577946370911))
edge.add_line((148.0000000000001, 108.9577946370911), (148.0000000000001, 104.3364804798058))
edge.add_spline(control_points=[(147.9999999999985, 104.3364804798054), (148.679990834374, 104.514372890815), (149.3460233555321, 104.760213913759), (150, 105.0347979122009)], knot_values=[17.56549764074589, 17.56549764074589, 17.56549764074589, 17.56549764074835, 19.56672786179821, 19.56672786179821, 19.56672786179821, 19.56672786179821], degree=3, periodic=0)
edge.add_line((150.0000000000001, 105.0347979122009), (150.0000000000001, 108.4577946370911))
edge = h.paths.add_edge_path()
edge.add_line((152.0000000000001, 108.9577946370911), (150.5000000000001, 108.9577946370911))
edge.add_line((150.5000000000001, 108.9577946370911), (150.0000000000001, 108.4577946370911))
edge.add_line((150.0000000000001, 108.4577946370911), (150.0000000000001, 105.0347979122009))
edge.add_spline(control_points=[(150, 105.0347979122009), (150.6789513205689, 105.319867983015), (151.344908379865, 105.6359182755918), (151.9999999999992, 105.939077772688)], knot_values=[19.56672786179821, 19.56672786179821, 19.56672786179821, 19.56672786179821, 21.64438294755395, 21.64438294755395, 21.64438294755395, 21.64438294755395], degree=3, periodic=0)
edge.add_line((152.0000000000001, 105.9390777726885), (152.0000000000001, 108.9577946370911))
h = msp.add_hatch(dxfattribs=at)
h.set_pattern_fill('ANSI31', scale=0.2, style=0)
h.set_pattern_definition([(45, (0, 0), (-0.4490128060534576, 0.4490128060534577), [])])
edge = h.paths.add_edge_path()
edge.add_arc((102.875, 96.90779463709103), 0.2249999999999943, 0, 180, ccw=False)
edge.add_line((103.1, 96.90779463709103), (103.1, 94.40779463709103))
edge.add_line((103.1, 94.40779463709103), (103.55, 94.40779463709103))
edge.add_line((103.55, 94.40779463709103), (103.55, 96.90779463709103))
edge.add_arc((102.875, 96.90779463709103), 0.6750000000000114, 0, 180)
edge.add_line((102.2, 96.90779463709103), (102.2, 94.18279463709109))
edge.add_arc((103.325, 94.18279463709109), 1.125, 180, 262.2266208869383)
edge.add_arc((103, 94.5077946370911), 1.450000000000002, 276.8458494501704, 360.0000147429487)
edge.add_line((104.45, 94.50779501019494), (104.4499998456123, 95.10779437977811))
edge.add_arc((105.4499998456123, 95.1077946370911), 0.9999999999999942, 90, 180.0000147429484, ccw=False)
edge.add_line((105.4499998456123, 96.10779463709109), (109.855185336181, 96.1077946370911))
edge.add_arc((109.855185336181, 95.1077946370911), 0.9999999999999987, 73.52002671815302, 90.0000000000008, ccw=False)
edge.add_line((110.1388655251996, 96.06671358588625), (121.7986449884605, 93.11736216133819))
edge.add_arc((122.2099812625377, 94.50779463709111), 1.450000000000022, 253.5200267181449, 270)
edge.add_line((122.2099812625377, 93.05779463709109), (137.5397852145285, 93.05779463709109))
edge.add_spline(control_points=[(137.5397852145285, 93.05779463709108), (137.5627773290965, 93.20743537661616), (137.5843313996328, 93.35746623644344), (137.6048188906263, 93.5077946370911)], knot_values=[0, 0, 0, 0, 0.4541903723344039, 0.4541903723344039, 0.4541903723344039, 0.4541903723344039], degree=3, periodic=0)
edge.add_line((137.6048188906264, 93.50779463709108), (132.2171286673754, 93.50779463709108))
edge.add_line((132.2171286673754, 93.50779463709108), (122.1448146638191, 93.5077946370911))
edge.add_arc((122.1448146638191, 94.5077946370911), 0.9999999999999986, 253.52002671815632, 269.9999999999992, ccw=False)
edge.add_line((121.8611344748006, 93.54887568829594), (110.2013550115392, 96.49822711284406))
edge.add_arc((109.7900187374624, 95.10779463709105), 1.450000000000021, 73.52002671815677, 89.99999999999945)
edge.add_line((109.7900187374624, 96.55779463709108), (105.45, 96.55779463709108))
edge.add_arc((105.45, 95.10779463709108), 1.450000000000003, 90.00000000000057, 180)
edge.add_line((104, 95.10779463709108), (104, 94.5077946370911))
edge.add_line((104, 94.5077946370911), (104, 94.40779463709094))
edge.add_arc((103.0620265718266, 94.48096639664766), 0.940823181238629, 306.7542392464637, 355.53936257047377, ccw=False)
edge.add_arc((103.25, 94.19554473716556), 0.5999999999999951, 180, 308.68218745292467, ccw=False)
edge.add_line((102.65, 94.19554473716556), (102.65, 94.40779463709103))
edge.add_line((102.65, 94.40779463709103), (102.65, 96.90779463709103))
h = msp.add_hatch(dxfattribs=at)
h.set_pattern_fill('ANSI37', scale=0.18, style=0)
h.set_pattern_definition([(45, (0, 0), (-0.4041115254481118, 0.4041115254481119), []), (135, (0, 0), (-0.4041115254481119, -0.4041115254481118), [])])
edge = h.paths.add_edge_path()
edge.add_line((120, 96.55779463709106), (120, 95.05779463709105))
edge.add_line((120, 95.05779463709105), (137.7925579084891, 95.05779463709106))
edge.add_spline(control_points=[(137.792557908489, 95.05779463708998), (137.8506767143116, 95.55912931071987), (137.9110420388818, 96.06025243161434), (137.9871730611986, 96.55779463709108)], knot_values=[2.008415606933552, 2.008415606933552, 2.008415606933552, 2.008415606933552, 3.5135742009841, 3.5135742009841, 3.5135742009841, 3.5135742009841], degree=3, periodic=0)
edge.add_line((137.9871730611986, 96.55779463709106), (120, 96.55779463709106))
edge = h.paths.add_edge_path()
edge.add_spline(control_points=[(137.6048188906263, 93.5077946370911), (137.6749264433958, 94.0222137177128), (137.7325444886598, 94.54011696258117), (137.792557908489, 95.05779463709)], knot_values=[0.4541903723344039, 0.4541903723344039, 0.4541903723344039, 0.4541903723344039, 2.008415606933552, 2.008415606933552, 2.008415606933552, 2.008415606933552], degree=3, periodic=0)
edge.add_line((137.7925579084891, 95.05779463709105), (120, 95.05779463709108))
edge.add_line((120, 95.05779463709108), (120, 94.69779463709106))
edge.add_line((120, 94.69779463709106), (120, 94.0196512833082))
edge.add_line((120, 94.0196512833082), (121.8611344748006, 93.54887568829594))
edge.add_arc((122.1448146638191, 94.5077946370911), 0.9999999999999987, 253.5200267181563, 270)
edge.add_line((122.1448146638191, 93.5077946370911), (137.6048188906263, 93.50779463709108))

# ---------------------------------------------------------------- linework, layer by layer
at = {"color": 1, "linetype": 'ACAD_ISO10W100', "lineweight": 25, "ltscale": 0.25}
for p, q in [((150, 115.2760053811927), (150, 189.6020107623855)), ((150, 114.8260053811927), (150, 189.1520107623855)), ((150, 114.6317892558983), (150, 188.9577946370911)), ((160, 169.3604644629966), (160, 185.4620360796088)), ((150.0000000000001, 95.45779463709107), (150.0000000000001, 120.4577946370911)), ((150, 40.94999999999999), (150, 115.2760053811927)), ((150, 114.6317892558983), (150, 89.63178925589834))]:
    msp.add_line(p, q, dxfattribs=at)
at = {"color": 7, "lineweight": 30, "ltscale": 0.25}
for p, q in [((146.5, 187.5758185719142), (153.5, 187.5758185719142)), ((146.5, 181.0554563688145), (146.5, 187.5758185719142)), ((153.5, 181.0554563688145), (153.5, 187.5758185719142)), ((146.5, 183.4577946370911), (145.5000000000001, 183.4577946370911)), ((144.0000000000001, 181.0554563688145), (144.0000000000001, 181.9577946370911)), ((145.5000000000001, 181.9577946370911), (146.5, 181.9577946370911)), ((145.5000000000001, 181.0554563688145), (145.5000000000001, 181.9577946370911)), ((146.5, 181.4624625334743), (153.5, 181.4624625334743)), ((153.5001429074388, 181.9577946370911), (153.7632577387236, 181.0554563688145)), ((155.3257264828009, 181.0554563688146), (154.9401717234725, 182.3776958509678)), ((157.032088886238, 182.2844799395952), (155.5, 181.0554563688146)), ((157.4177141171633, 181.8234116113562), (155.8732023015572, 180.5886377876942)), ((157.032088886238, 182.2844799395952), (157.4177141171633, 181.8234116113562)), ((142.5, 180.4577946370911), (142.5, 181.0554563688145)), ((142.5, 181.0554563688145), (146.5, 181.0554563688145)), ((146.5, 180.4577946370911), (142.5, 180.4577946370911)), ((144.0000000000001, 180.1577946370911), (144.0000000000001, 180.4577946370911)), ((145.5000000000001, 180.1577946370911), (145.5000000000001, 180.4577946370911)), ((149.9470806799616, 181.0554563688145), (146.5, 181.0554563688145)), ((150, 180.4577946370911), (146.5, 180.4577946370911)), ((149.9470806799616, 181.0554563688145), (153.5, 181.0554563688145)), ((150.0000000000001, 180.4577946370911), (153.5, 180.4577946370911)), ((153.5, 181.0554563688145), (155.5, 181.0554563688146)), ((153.5, 180.4577946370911), (155.5, 180.457794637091)), ((153.9931249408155, 180.2671390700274), (153.9375312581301, 180.4577946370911)), ((153.9931249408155, 180.2671390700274), (154.059971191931, 180.0378934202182)), ((155.9480184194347, 180.4577946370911), (155.5428323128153, 180.4577946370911)), ((165, 180.4577946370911), (155.9480184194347, 180.4577946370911)), ((165, 180.4577946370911), (165, 178.9577946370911)), ((144.0000000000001, 180.1577946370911), (145.5000000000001, 180.1577946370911)), ((150.0000000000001, 178.7577946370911), (149.0592363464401, 179.6985582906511)), ((150.9003744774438, 179.6581691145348), (150.0000000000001, 178.7577946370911)), ((150.937662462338, 179.6954570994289), (150.9287125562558, 179.6865071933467)), ((103.325, 178.9577946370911), (122.2099812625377, 178.9577946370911)), ((121.7986449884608, 178.898227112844), (110.1388655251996, 175.9488756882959)), ((121.8611344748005, 178.4667135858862), (110.2013550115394, 175.5173621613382)), ((141.5, 178.5077946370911), (122.1308111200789, 178.5077946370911)), ((133, 178.5077946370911), (122.1448146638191, 178.5077946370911)), ((122.2099812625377, 178.9577946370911), (133, 178.9577946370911)), ((136, 178.9577946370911), (133, 178.9577946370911)), ((136, 178.5077946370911), (133, 178.5077946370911)), ((142.5, 178.9577946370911), (136, 178.9577946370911)), ((141.5817541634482, 178.5077946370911), (136, 178.5077946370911)), ((141.5, 178.5077946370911), (141.5, 176.6477946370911)), ((142.5, 178.9577946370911), (145.272421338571, 178.9577946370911)), ((142.5, 178.9577946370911), (142.5, 178.7077946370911)), ((143.9625441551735, 178.5077946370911), (142.5417424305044, 178.5077946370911)), ((143.5, 178.2077946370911), (143, 178.2077946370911)), ((143.95, 178.9577946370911), (143.95, 103.6632302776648)), ((143.95, 178.9577946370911), (144.5, 178.9577946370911)), ((145, 178.4577946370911), (144.5, 178.9577946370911)), ((144.5, 178.9577946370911), (145.272421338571, 178.9577946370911)), ((145, 178.4577946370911), (145.0900000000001, 178.4577946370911)), ((145, 103.8260032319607), (145, 178.4577946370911)), ((145.5400000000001, 178.2875873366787), (145.5400000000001, 165.2577946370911)), ((154.4600000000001, 178.2875873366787), (154.4600000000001, 165.2577946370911)), ((157.5, 178.9577946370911), (154.7275786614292, 178.9577946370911)), ((154.7275786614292, 178.9577946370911), (155.5, 178.9577946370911)), ((155, 178.4577946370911), (154.9100000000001, 178.4577946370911)), ((155, 178.4577946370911), (155.5, 178.9577946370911)), ((155, 107.0985468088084), (155, 178.4577946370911)), ((156.05, 178.9577946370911), (155.5, 178.9577946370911)), ((164, 178.9577946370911), (156, 178.9577946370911)), ((156.05, 178.9577946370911), (156.05, 107.2761614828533)), ((156.5, 178.2077946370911), (157, 178.2077946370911)), ((177.7900187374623, 178.9577946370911), (157.5, 178.9577946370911)), ((157.5, 178.9577946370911), (157.5, 178.7077946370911)), ((158.4182458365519, 178.5077946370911), (177.8551853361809, 178.5077946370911)), ((177.8562475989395, 178.5077946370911), (158.5, 178.5077946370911)), ((158.5, 178.5077946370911), (158.5, 176.6477946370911)), ((196.675, 178.9577946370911), (177.7900187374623, 178.9577946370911)), ((189.7986449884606, 175.5173621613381), (178.1388655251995, 178.4667135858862)), ((178.2013550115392, 178.898227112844), (189.8611344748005, 175.9488756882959)), ((120, 177.995937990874), (120, 176.6477946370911)), ((142.55, 177.7577946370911), (143.05, 177.7577946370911)), ((143.55, 177.2577946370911), (143.55, 174.9577946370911)), ((143.95, 174.9577946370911), (143.95, 177.7077946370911)), ((156.05, 174.9577946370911), (156.05, 177.7077946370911)), ((156.45, 177.2577946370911), (156.45, 174.9577946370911)), ((157.45, 177.7577946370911), (156.95, 177.7577946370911)), ((180, 176.6477946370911), (180, 177.995937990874)), ((195.55, 177.5077946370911), (195.55, 177.5077946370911)), ((195.5500001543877, 176.9077947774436), (195.55, 177.5077942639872)), ((196, 176.9077946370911), (196, 177.5077946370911)), ((196.45, 175.1077946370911), (196.45, 177.6077946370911)), ((196.45, 177.6077946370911), (196.9, 177.6077946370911)), ((196.9, 177.6077946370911), (196.9, 175.1077946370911)), ((197.35, 177.6077946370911), (197.35, 177.8200445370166)), ((197.35, 175.1077946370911), (197.35, 177.6077946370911)), ((197.8, 175.1077946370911), (197.8, 177.832794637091)), ((120, 177.032794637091), (132.4814918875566, 177.032794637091)), ((120, 176.6477946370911), (120, 175.557794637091)), ((136.5185081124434, 177.032794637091), (132.4814918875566, 177.032794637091)), ((136.5185081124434, 177.032794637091), (143.55, 177.032794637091)), ((141.5, 176.6477946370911), (141.5, 175.5577946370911)), ((156.45, 177.0327946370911), (180, 177.0327946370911)), ((158.5, 176.6477946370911), (158.5, 175.5577946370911)), ((180, 176.6477946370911), (180, 175.5577946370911)), ((196, 176.9077946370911), (196, 103.7205278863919)), ((106, 175.557794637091), (143.55, 175.557794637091)), ((109.7900187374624, 175.4577946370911), (143.55, 175.4577946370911)), ((143.5, 173.5577946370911), (141.5, 175.5577946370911)), ((143.55, 174.9577946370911), (143.95, 174.9577946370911)), ((156.45, 174.9577946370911), (156.05, 174.9577946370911)), ((156.45, 175.557794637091), (194, 175.5577946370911)), ((190.2099812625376, 175.4577946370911), (156.45, 175.4577946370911)), ((158.5, 175.5577946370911), (156.5, 173.5577946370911)), ((190.144814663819, 175.9077946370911), (194.5500001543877, 175.9077946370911)), ((190.2099812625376, 175.4577946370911), (194.55, 175.4577946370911)), ((196.45, 97.58279453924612), (196.45, 175.1077946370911)), ((196.9, 175.1077946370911), (197.35, 175.1077946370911)), ((195.5, 174.0577946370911), (195.5, 103.8812710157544)), ((143.95, 173.5577946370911), (143.5, 173.5577946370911)), ((143.5, 103.5745058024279), (143.5, 173.5577946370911)), ((156.5, 173.5577946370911), (156.05, 173.5577946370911)), ((156.5, 173.5577946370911), (156.5, 107.293329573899)), ((145.5400000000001, 165.2577946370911), (154.4600000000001, 165.2577946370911)), ((154.4600000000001, 121.7577946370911), (145.5400000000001, 121.7577946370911)), ((145.5400000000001, 121.7577946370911), (145.5400000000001, 108.9577946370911)), ((150.0000000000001, 120.7577946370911), (149.0000000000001, 121.7577946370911)), ((151.0000000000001, 121.7577946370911), (150.0000000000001, 120.7577946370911)), ((154.4600000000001, 121.7577946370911), (154.4600000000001, 108.9577946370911)), ((148.0000000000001, 108.9577946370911), (148.0000000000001, 104.3364804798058)), ((148.0000000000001, 108.9577946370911), (152.0000000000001, 108.9577946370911)), ((149.5000000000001, 108.9577946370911), (150.0000000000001, 108.4577946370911)), ((150.0000000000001, 108.4577946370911), (150.5000000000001, 108.9577946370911)), ((152.0000000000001, 108.9577946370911), (152.0000000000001, 105.9390777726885)), ((197.1249999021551, 97.58279463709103), (138.172001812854, 97.58279463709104)), ((197.8, 96.90779463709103), (197.8, 94.18279463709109)), ((121.7986449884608, 93.11736216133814), (110.1388655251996, 96.06671358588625)), ((110.2013550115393, 96.49822711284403), (121.8611344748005, 93.54887568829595)), ((110.8087323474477, 96.55779463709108), (137.9871730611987, 96.55779463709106)), ((111.2162555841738, 96.55779463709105), (137.9871730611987, 96.55779463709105)), ((120, 96.55779463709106), (120, 94.69779463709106)), ((137.9871730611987, 96.55779463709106), (120, 96.55779463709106)), ((120, 95.05779463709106), (137.7925579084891, 95.05779463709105)), ((120, 94.69779463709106), (120, 94.0196512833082)), ((137.6048188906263, 93.50779463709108), (122.1448146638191, 93.5077946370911)), ((103.3185330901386, 93.05779463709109), (122.2099812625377, 93.05779463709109)), ((122.2099812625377, 93.05779463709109), (137.5397852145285, 93.05779463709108)), ((158.5, 93.05779463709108), (137.5397852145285, 93.05779463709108)), ((141.5, 93.05779463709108), (141.5, 91.05779463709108)), ((141.5, 92.60779463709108), (141.5, 93.05779463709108)), ((141.5, 93.05779463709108), (141.5010905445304, 93.05779463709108)), ((177.7900187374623, 93.05779463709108), (158.5, 93.05779463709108)), ((158.5, 93.05779463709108), (158.5, 91.05779463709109)), ((158.5, 93.05779463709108), (158.5, 92.60779463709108)), ((196.675, 93.05779463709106), (177.7900187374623, 93.05779463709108)), ((143.5, 91.05779463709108), (141.5, 91.05779463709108)), ((146.5, 91.05779463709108), (155.2953614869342, 91.05779463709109)), ((158.5, 91.05779463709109), (155.2953614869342, 91.05779463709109)), ((156, 91.05779463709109), (156, 89.05779463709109)), ((135, 89.05779463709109), (165, 89.05779463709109)), ((135, 89.05779463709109), (135, 87.55779463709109)), ((165, 87.55779463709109), (165, 89.05779463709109)), ((135, 87.55779463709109), (146.0551584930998, 87.55779463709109)), ((146.0551584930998, 87.55779463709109), (135.3, 87.55779463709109)), ((146.0551584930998, 87.55779463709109), (147.4551611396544, 87.55779463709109)), ((147.5, 87.55779463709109), (147.4551611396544, 87.55779463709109)), ((147.5, 87.55779463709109), (165, 87.55779463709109)), ((164.7, 87.55779463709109), (147.5, 87.55779463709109)), ((165.4999997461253, 87.95779463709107), (166.9000030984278, 87.9577946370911)), ((165.5, 86.75779463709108), (165.4999997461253, 87.9577946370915)), ((166.9000030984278, 87.9577946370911), (166.9000030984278, 86.05779463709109)), ((134.5, 86.75779463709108), (134.5000007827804, 83.05779463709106)), ((167.5000030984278, 86.05779463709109), (154.4000030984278, 86.05779463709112)), ((165.5, 86.75779463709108), (165.5, 86.05779463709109)), ((167.5000030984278, 86.05779463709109), (167.5000030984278, 83.05779463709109)), ((116.1, 83.05779463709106), (131.5, 83.05779463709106)), ((131.5, 83.05779463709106), (146.5, 83.05779463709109)), ((146.5, 83.05779463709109), (167.5000030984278, 83.05779463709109)), ((167.5000030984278, 83.05779463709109), (169.0000030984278, 83.05779463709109)), ((169.0000030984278, 83.05779463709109), (169.0000030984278, 68.05779463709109))]:
    msp.add_line(p, q, dxfattribs=at)
at = {"color": 7, "linetype": 'ByBlock', "lineweight": 15}
for p, q in [((150.0000000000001, 178.7577946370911), (150.9287125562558, 179.6865071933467)), ((145.5400000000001, 108.9577946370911), (154.4600000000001, 108.9577946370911))]:
    msp.add_line(p, q, dxfattribs=at)
at = {"color": 7, "lineweight": 15, "ltscale": 0.25}
for p, q in [((141.5, 176.6477946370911), (141.5, 178.5077946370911)), ((120, 177.995937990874), (120, 176.6477946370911)), ((143.95, 174.5577946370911), (143.55, 174.9577946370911)), ((156.05, 174.5577946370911), (156.45, 174.9577946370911)), ((76.02203149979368, 171.0874822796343), (148.2039487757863, 156.2775385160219)), ((154.5900000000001, 106.9857708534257), (154.2500000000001, 106.8772143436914)), ((145.4250000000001, 103.8835345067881), (145.0900000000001, 103.8383460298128)), ((120, 96.55779463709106), (120, 94.69779463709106)), ((137.9871730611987, 96.55779463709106), (120, 96.55779463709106)), ((137.6048188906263, 93.50779463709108), (132.2171286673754, 93.50779463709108)), ((155.2953614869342, 91.05779463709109), (155.2953614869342, 89.05779463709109))]:
    msp.add_line(p, q, dxfattribs=at)
at = {"color": 7, "linetype": 'ByBlock', "lineweight": 30}
for p, q in [((145.0900000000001, 107.7577946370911), (145.0900000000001, 178.8252827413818)), ((145.4250000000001, 107.7577946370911), (145.4250000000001, 178.2008052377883)), ((154.5750000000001, 107.7577946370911), (154.5750000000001, 178.2008052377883)), ((154.9100000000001, 107.7577946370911), (154.9100000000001, 178.8252827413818)), ((145.4250000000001, 108.9577946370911), (154.5750000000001, 108.9577946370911)), ((145.4250000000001, 108.9577946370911), (145.4250000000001, 107.7577946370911)), ((145.4250000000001, 108.9577946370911), (145.4250000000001, 107.7577946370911)), ((148.0000000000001, 108.9577946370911), (148.0000000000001, 104.3364804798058)), ((152.0000000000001, 108.9577946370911), (152.0000000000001, 105.9390777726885)), ((154.5750000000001, 108.9577946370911), (154.5750000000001, 107.7577946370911)), ((154.5750000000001, 108.9577946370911), (154.5750000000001, 107.7577946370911)), ((145.7500000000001, 107.7577946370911), (145.4250000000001, 107.7577946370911)), ((145.7500000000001, 107.7577946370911), (145.7500000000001, 104.2577946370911)), ((154.2500000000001, 107.7577946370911), (154.5750000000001, 107.7577946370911)), ((154.2500000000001, 107.7577946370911), (154.2500000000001, 106.8772143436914)), ((145.4100000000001, 107.2064326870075), (145.4100000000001, 104.8091565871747)), ((154.5900000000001, 107.2064326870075), (154.5900000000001, 106.9857708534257)), ((145.0900000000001, 103.8383460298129), (145.0900000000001, 104.2577946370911)), ((145.4250000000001, 104.2577946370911), (145.7500000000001, 104.2577946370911)), ((145.4250000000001, 103.8835345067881), (145.4250000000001, 104.2577946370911)), ((145.4250000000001, 103.8835345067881), (145.4250000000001, 104.2577946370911)), ((145.4250000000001, 103.8835345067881), (145.4250000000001, 104.2577946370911))]:
    msp.add_line(p, q, dxfattribs=at)
at = {"color": 7, "lineweight": 30, "ltscale": 0.25}
for centre, radius, start, end in [((145.5000000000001, 181.9577946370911), 1.5, 90, 180), ((153.5001429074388, 181.9577946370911), 1.500000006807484, 16.25627409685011, 89.99454133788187), ((160.0000000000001, 180.457794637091), 2.5, 0, 180), ((155.5, 181.0554563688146), 0.5976617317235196, 270, 308.6409015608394), ((155.5, 180.4577946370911), 1.5, 196.2562742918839, 270), ((122.2099812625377, 177.5077946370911), 1.45, 90, 106.4799732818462), ((122.1448146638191, 177.5077946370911), 1, 90, 106.4799732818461), ((141.5817541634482, 178.0077946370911), 0.5, 14.47751218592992, 90), ((142.55, 178.2577946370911), 0.5, 194.47751218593, 270), ((143, 178.7077946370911), 0.5, 180, 270), ((143.45, 177.7077946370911), 0.5, 0, 90.0000000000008), ((156.55, 177.7077946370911), 0.5, 89.99999999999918, 180), ((157, 178.7077946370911), 0.5, 270, 0), ((157.45, 178.2577946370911), 0.5, 270, 345.5224878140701), ((158.4182458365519, 178.0077946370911), 0.5, 89.99999999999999, 165.5224878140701), ((177.7900187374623, 177.5077946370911), 1.45, 73.52002671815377, 89.99999999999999), ((177.8551853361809, 177.5077946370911), 1, 73.52002671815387, 89.99999999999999), ((197, 177.5077946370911), 1.45, 96.8458494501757, 180), ((197, 177.5077946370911), 1, 128.6821874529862, 180), ((196.75, 177.8200445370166), 0.6, 0, 128.6821874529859), ((196.675, 177.832794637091), 1.125, 0, 89.99999999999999), ((143.05, 177.2577946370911), 0.5, 0, 90), ((156.95, 177.2577946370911), 0.5, 89.99999999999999, 180), ((196.675, 177.6077946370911), 0.2250000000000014, 0, 180), ((194.55, 176.9077946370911), 1.45, 270, 0), ((194.5500001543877, 176.9077946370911), 1, 270, 8.041605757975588e-06), ((190.2099812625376, 176.9077946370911), 1.45, 253.5200267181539, 270.0000000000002), ((190.144814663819, 176.9077946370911), 1, 253.5200267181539, 270), ((194, 174.0577946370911), 1.5, 0, 90), ((197.125, 175.1077946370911), 0.6750000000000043, 180, 0), ((197.125, 175.1077946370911), 0.2250000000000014, 180, 0), ((197.125, 96.90779463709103), 0.6750000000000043, 0, 90.00000830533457), ((122.1448146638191, 94.5077946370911), 1, 253.5200267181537, 270), ((196.675, 94.18279463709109), 1.125, 270, 0), ((122.2099812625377, 94.5077946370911), 1.45, 253.5200267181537, 270), ((145, 89.05779463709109), 2.5, 0, 180), ((160, 89.05779463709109), 2.5, 0, 180), ((135.3, 86.75779463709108), 0.8, 90, 180), ((164.7, 86.75779463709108), 0.8, 0, 90), ((154.4000030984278, 82.05779463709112), 4, 90, 165.5224878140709)]:
    msp.add_arc(centre, radius, start, end, dxfattribs=at)
at = {"color": 7, "linetype": 'ByBlock', "lineweight": 30}
for centre, radius, start, end in [((150.0000000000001, 172.2577946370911), 8.200000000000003, 53.21739364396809, 126.7826063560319), ((150.0000000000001, 172.2577946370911), 7.5, 52.41049703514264, 127.5895029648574), ((145.4250000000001, 107.7577946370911), 0.3350000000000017, 180, 240.2601303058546), ((145.1100000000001, 107.2064326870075), 0.3, 0, 60.26013030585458), ((145.5500000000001, 107.5577946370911), 0.2000000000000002, 0, 90), ((154.4500000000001, 107.5577946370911), 0.2000000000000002, 90, 180), ((154.8900000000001, 107.2064326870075), 0.3, 119.7398696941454, 180), ((154.5750000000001, 107.7577946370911), 0.3350000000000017, 299.7398696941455, 0), ((145.4250000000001, 104.2577946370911), 0.3350000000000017, 119.7398696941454, 180), ((145.1100000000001, 104.8091565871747), 0.3, 299.7398696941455, 0), ((145.5500000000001, 104.4577946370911), 0.2000000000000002, 270, 0)]:
    msp.add_arc(centre, radius, start, end, dxfattribs=at)
at = {"color": 7, "lineweight": 15, "ltscale": 0.25}
for points, knots in [([(154.5900000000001, 106.9857708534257), (155.2342828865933, 107.1792284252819), (158.9682454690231, 107.8731789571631), (166.2472937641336, 100.5987291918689), (177.8374551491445, 99.56551382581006), (187.5159383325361, 102.123360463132), (193.9734181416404, 104.7820609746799), (196.45, 103.5202772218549)], [24.4393713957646, 24.4393713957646, 24.4393713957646, 24.4393713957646, 26.56510633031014, 36.92141533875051, 50.22349476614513, 59.82893242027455, 68.16739771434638, 68.16739771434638, 68.16739771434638, 68.16739771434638]), ([(145.4250000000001, 103.8835345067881), (146.2794498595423, 103.9980840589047), (149.4161384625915, 104.4164293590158), (152.270482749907, 106.2092175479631), (154.2500000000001, 106.8772143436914)], [15.06573433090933, 15.06573433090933, 15.06573433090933, 15.06573433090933, 17.56549764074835, 24.06630626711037, 24.06630626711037, 24.06630626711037, 24.06630626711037]), ([(137.5397852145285, 93.05779463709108), (137.8876004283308, 95.32149794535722), (137.9163006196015, 98.92745300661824), (141.1019672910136, 103.214593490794), (143.6599470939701, 103.6431965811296), (145.0900000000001, 103.8383460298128)], [0, 0, 0, 0, 6.870804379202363, 10.52954648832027, 14.73811989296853, 14.73811989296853, 14.73811989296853, 14.73811989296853])]:
    msp.add_open_spline(points, degree=3, knots=knots, dxfattribs=at)

# ---------------------------------------------------------------- block references
at = {"color": 7, "linetype": 'ByBlock', "lineweight": 15, "rotation": 180}
for p in [(150.0000000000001, 165.2577946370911), (150.0000000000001, 150.7577946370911), (150.0000000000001, 136.2577946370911)]:
    msp.add_blockref('tetril_stolbik_8_92', p, dxfattribs=at)

doc.saveas('drawing.dxf')
